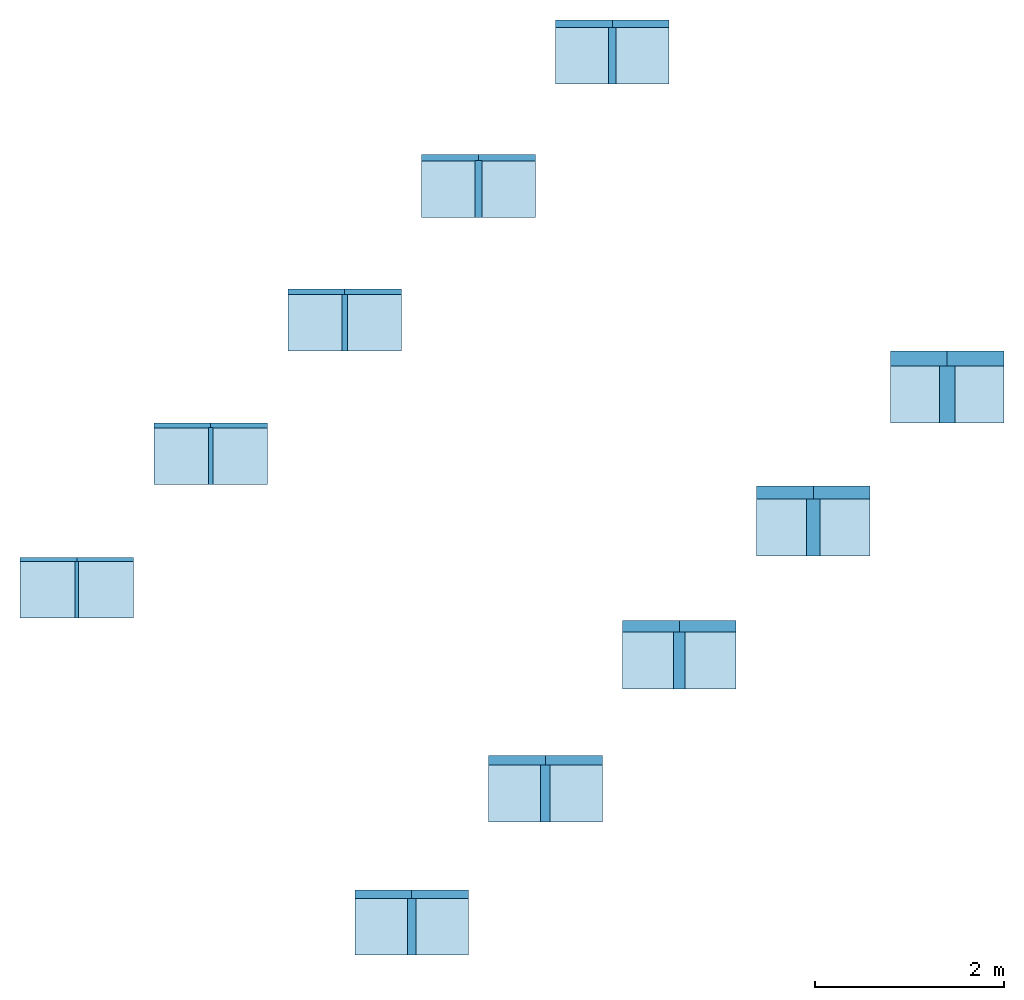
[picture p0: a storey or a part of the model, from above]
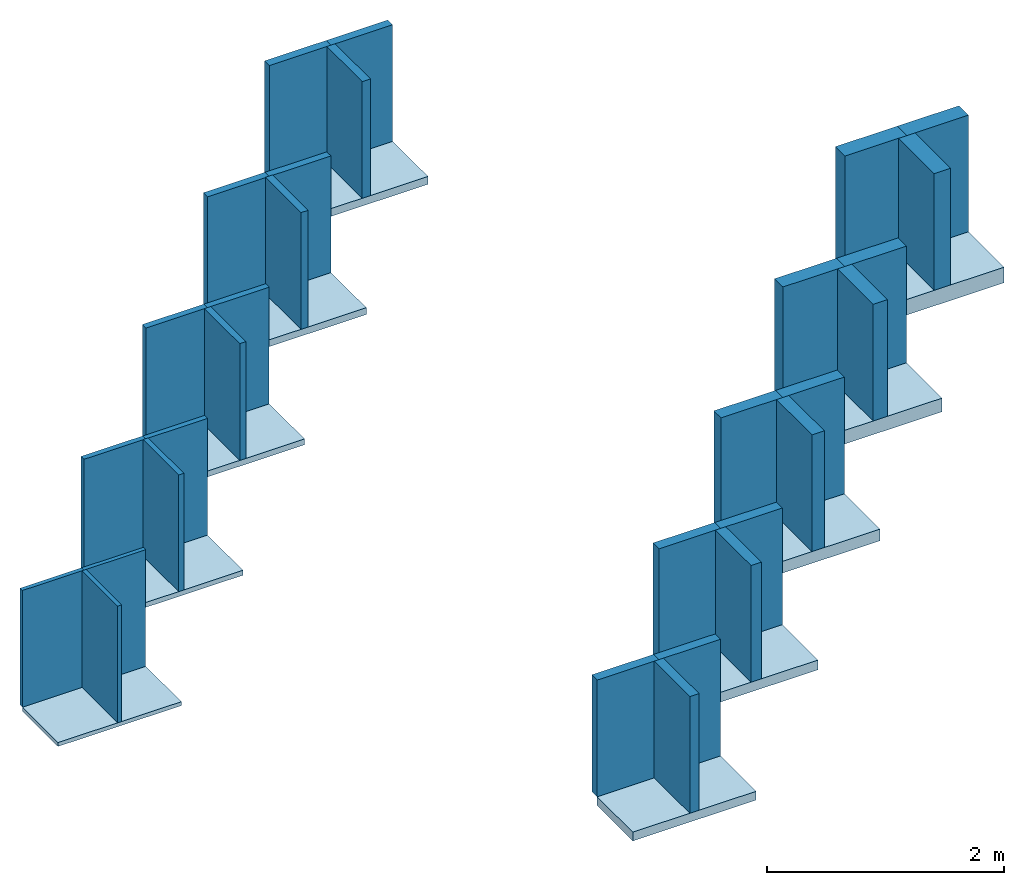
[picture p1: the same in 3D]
Properties of the parts of a building model (IFC2X3), part 1 of 2

# File
Description: ViewDefinition [CoordinationView]
Time: 2023-01-18T13:19:17
Written by: The EXPRESS Data Manager Version 5.02.0100.07 : 28 Aug 2013
Made in: 21.1.70.21 - Exporter 21.1.70.21 - Alternate UI 21.1.70.21
Comment: STEP Physical File produced by: The EXPRESS Data Manager Version 5.02.0100.07 : 28 Aug 2013 * Module: EDMstepFileFactory/EDMstandAlone * Creation date: Wed Jan 18 13:19:17 2023 * Host: BIM-LT03 * Database: C:\Users\DONNEE~1\AppData\Local\Temp\6dfd9f73-01cb-4fe2-bb7c-203e315a706e\f2f63303-374b-483b-9fe5-4dce5f40f722\ifc * Database version: 5507 * Database creation date: Wed Jan 18 13:19:16 2023 * Schema: IFC2X3 * Model: DataRepository.ifc * Model creation date: Wed Jan 18 13:19:16 2023 * Header model: DataRepository.ifc_HeaderModel * Header model creation date: Wed Jan 18 13:19:16 2023 * EDMuser: sdai-user * EDMgroup: sdai-group * License ID and type: 5605 : Permanent license. Expiry date: * EDMstepFileFactory options: 020000

# IfcSite, Default
RefLatitude: 42, 24, 53, 508911; RefLongitude: -71, -15, -29, -58837; RefElevation: 0 mm
Pset_ProductRequirements - Category: Project Information

# IfcBuilding
Pset_BuildingCommon - NumberOfStoreys: 2
Pset_ProductRequirements - Category: Project Information

# IfcBuildingStorey: Level:NL_00_niveau (2)
Pset_ProductRequirements - Category: Levels
Name | LongName = Pset_AirSideSystemInformation, Name = Pset_ProductRequirements, Name | Elevation (mm)
Begane grond | Begane grond | 0
lengte 1200 | lengte 1200 | 1200

# IfcRoof: Basic Roof:NLRS_27_RO_Rock4all_100x600x1200mm, Basic Roof:NLRS_27_RO_Rock4all_100x600x1200mm:5487
In: lengte 1200
Classification: 27 Daken (Uniformat)
Pset_ElementShading - Roughness: 304.8 mm
Pset_ManufacturerTypeInformation - Manufacturer: Knauf Insulation B.V.
Pset_ProductRequirements - Category: Roofs
Pset_QuantityTakeOff - Reference: Basic Roof:NLRS_27_RO_Rock4all_100x600x1200mm
Pset_RoofCommon - IsExternal: yes; Reference: Basic Roof:NLRS_27_RO_Rock4all_100x600x1200mm; ProjectedArea: 0.72 m2; TotalArea: 0.72 m2
Pset_Roof Schedule Rock4All LOD400 - platen / pak: 5; Type: Basic Roof: NLRS_27_RO_Rock4all_100x600x1200mm; Assembly Code: 27; Type Image: Raster image: Rock4all_KL.jpg (3); Model: Rock4All is een onbeklede steenwolplaat met ECOSE® Technology; Manufacturer: Knauf Insulation B.V.; URL: www.knaufinsulation.nl; Description: Rock4all - 100mm; phone: +31(0)162-421245; email: customerservice.nl@knaufinsulation.com; product URL: https://www.knaufinsulation.nl/producten-van-knauf-insulation/Rock4All; warmteweerstand: 2.85; NLRS_C_Code_Brandklasse: A1; warmtegeleidingscoëfficiënt: 0.035; waterdamptransmissie / waterdampdiffusie weerstandsfactor: MU1; luchtstroomweerstand: Afr5; DoP nummer (Declaration of performance): R4208LPCPR; diktebereik: 20-200; diktetolerantie: T4; pak (m2): 3.6; pakken / pallet: 12; pallet (m2): 43.2

# IfcRoof: Basic Roof:NLRS_27_RO_Rock4all_120x600x1200mm, Basic Roof:NLRS_27_RO_Rock4all_120x600x1200mm:5557
In: lengte 1200
Classification: 27 Daken (Uniformat)
Pset_ElementShading - Roughness: 304.8 mm
Pset_ManufacturerTypeInformation - Manufacturer: Knauf Insulation B.V.
Pset_ProductRequirements - Category: Roofs
Pset_QuantityTakeOff - Reference: Basic Roof:NLRS_27_RO_Rock4all_120x600x1200mm
Pset_RoofCommon - IsExternal: yes; Reference: Basic Roof:NLRS_27_RO_Rock4all_120x600x1200mm; ProjectedArea: 0.72 m2; TotalArea: 0.72 m2
Pset_Roof Schedule Rock4All LOD400 - platen / pak: 4; Type: Basic Roof: NLRS_27_RO_Rock4all_120x600x1200mm; Assembly Code: 27; Type Image: Raster image: Rock4all_KL.jpg (3); Model: Rock4All is een onbeklede steenwolplaat met ECOSE® Technology; Manufacturer: Knauf Insulation B.V.; URL: www.knaufinsulation.nl; Description: Rock4all - 120mm; phone: +31(0)162-421245; email: customerservice.nl@knaufinsulation.com; product URL: https://www.knaufinsulation.nl/producten-van-knauf-insulation/Rock4All; warmteweerstand: 3.4; NLRS_C_Code_Brandklasse: A1; warmtegeleidingscoëfficiënt: 0.035; waterdamptransmissie / waterdampdiffusie weerstandsfactor: MU1; luchtstroomweerstand: Afr5; DoP nummer (Declaration of performance): R4208LPCPR; diktebereik: 20-200; diktetolerantie: T4; pak (m2): 2.88; pakken / pallet: 12; pallet (m2): 34.56

# IfcRoof: Basic Roof:NLRS_27_RO_Rock4all_140x600x1200mm, Basic Roof:NLRS_27_RO_Rock4all_140x600x1200mm:5576
In: lengte 1200
Classification: 27 Daken (Uniformat)
Pset_ElementShading - Roughness: 304.8 mm
Pset_ManufacturerTypeInformation - Manufacturer: Knauf Insulation B.V.
Pset_ProductRequirements - Category: Roofs
Pset_QuantityTakeOff - Reference: Basic Roof:NLRS_27_RO_Rock4all_140x600x1200mm
Pset_RoofCommon - IsExternal: yes; Reference: Basic Roof:NLRS_27_RO_Rock4all_140x600x1200mm; ProjectedArea: 0.72 m2; TotalArea: 0.72 m2
Pset_Roof Schedule Rock4All LOD400 - warmteweerstand: 4; platen / pak: 3; Type: Basic Roof: NLRS_27_RO_Rock4all_140x600x1200mm; Assembly Code: 27; Type Image: Raster image: Rock4all_KL.jpg (3); Model: Rock4All is een onbeklede steenwolplaat met ECOSE® Technology; Manufacturer: Knauf Insulation B.V.; URL: www.knaufinsulation.nl; Description: Rock4all - 140mm; phone: +31(0)162-421245; email: customerservice.nl@knaufinsulation.com; product URL: https://www.knaufinsulation.nl/producten-van-knauf-insulation/Rock4All; NLRS_C_Code_Brandklasse: A1; warmtegeleidingscoëfficiënt: 0.035; waterdamptransmissie / waterdampdiffusie weerstandsfactor: MU1; luchtstroomweerstand: Afr5; DoP nummer (Declaration of performance): R4208LPCPR; diktebereik: 20-200; diktetolerantie: T4; pak (m2): 2.16; pakken / pallet: 12; pallet (m2): 25.92

# IfcRoof: Basic Roof:NLRS_27_RO_Rock4all_160x600x1200mm, Basic Roof:NLRS_27_RO_Rock4all_160x600x1200mm:5595
In: lengte 1200
Classification: 27 Daken (Uniformat)
Pset_ElementShading - Roughness: 304.8 mm
Pset_ManufacturerTypeInformation - Manufacturer: Knauf Insulation B.V.
Pset_ProductRequirements - Category: Roofs
Pset_QuantityTakeOff - Reference: Basic Roof:NLRS_27_RO_Rock4all_160x600x1200mm
Pset_RoofCommon - IsExternal: yes; Reference: Basic Roof:NLRS_27_RO_Rock4all_160x600x1200mm; ProjectedArea: 0.72 m2; TotalArea: 0.72 m2
Pset_Roof Schedule Rock4All LOD400 - platen / pak: 3; Type: Basic Roof: NLRS_27_RO_Rock4all_160x600x1200mm; Assembly Code: 27; Type Image: Raster image: Rock4all_KL.jpg (3); Model: Rock4All is een onbeklede steenwolplaat met ECOSE® Technology; Manufacturer: Knauf Insulation B.V.; URL: www.knaufinsulation.nl; Description: Rock4all - 160mm; phone: +31(0)162-421245; email: customerservice.nl@knaufinsulation.com; product URL: https://www.knaufinsulation.nl/producten-van-knauf-insulation/Rock4All; warmteweerstand: 4.55; NLRS_C_Code_Brandklasse: A1; warmtegeleidingscoëfficiënt: 0.035; waterdamptransmissie / waterdampdiffusie weerstandsfactor: MU1; luchtstroomweerstand: Afr5; DoP nummer (Declaration of performance): R4208LPCPR; diktebereik: 20-200; diktetolerantie: T4; pak (m2): 2.16; pakken / pallet: 12; pallet (m2): 25.92

# IfcRoof: Basic Roof:NLRS_27_RO_Rock4all_40x600x1200mm, Basic Roof:NLRS_27_RO_Rock4all_40x600x1200mm:5042
In: lengte 1200
Classification: 27 Daken (Uniformat)
Pset_ElementShading - Roughness: 304.8 mm
Pset_ManufacturerTypeInformation - Manufacturer: Knauf Insulation B.V.
Pset_ProductRequirements - Category: Roofs
Pset_QuantityTakeOff - Reference: Basic Roof:NLRS_27_RO_Rock4all_40x600x1200mm
Pset_RoofCommon - Reference: Basic Roof:NLRS_27_RO_Rock4all_40x600x1200mm; IsExternal: yes; ProjectedArea: 0.72 m2; TotalArea: 0.72 m2
Pset_Roof Schedule Rock4All LOD400 - Type: Basic Roof: NLRS_27_RO_Rock4all_40x600x1200mm; Assembly Code: 27; Type Image: Raster image: Rock4all_KL.jpg (3); Model: Rock4All is een onbeklede steenwolplaat met ECOSE® Technology; Manufacturer: Knauf Insulation B.V.; URL: www.knaufinsulation.nl; Description: Rock4all - 40mm; phone: +31(0)162-421245; email: customerservice.nl@knaufinsulation.com; product URL: https://www.knaufinsulation.nl/producten-van-knauf-insulation/Rock4All; warmteweerstand: 1.1; NLRS_C_Code_Brandklasse: A1; warmtegeleidingscoëfficiënt: 0.035; waterdamptransmissie / waterdampdiffusie weerstandsfactor: MU1; luchtstroomweerstand: Afr5; DoP nummer (Declaration of performance): R4208LPCPR; diktebereik: 20-200; diktetolerantie: T4; platen / pak: 12; pak (m2): 8.64; pakken / pallet: 12; pallet (m2): 103.68

# IfcRoof: Basic Roof:NLRS_27_RO_Rock4all_50x600x1200mm, Basic Roof:NLRS_27_RO_Rock4all_50x600x1200mm:5238
In: lengte 1200
Classification: 27 Daken (Uniformat)
Pset_ElementShading - Roughness: 304.8 mm
Pset_ManufacturerTypeInformation - Manufacturer: Knauf Insulation B.V.
Pset_ProductRequirements - Category: Roofs
Pset_QuantityTakeOff - Reference: Basic Roof:NLRS_27_RO_Rock4all_50x600x1200mm
Pset_RoofCommon - IsExternal: yes; Reference: Basic Roof:NLRS_27_RO_Rock4all_50x600x1200mm; ProjectedArea: 0.72 m2; TotalArea: 0.72 m2
Pset_Roof Schedule Rock4All LOD400 - platen / pak: 10; Type: Basic Roof: NLRS_27_RO_Rock4all_50x600x1200mm; Assembly Code: 27; Type Image: Raster image: Rock4all_KL.jpg (3); Model: Rock4All is een onbeklede steenwolplaat met ECOSE® Technology; Manufacturer: Knauf Insulation B.V.; URL: www.knaufinsulation.nl; Description: Rock4all - 50mm; phone: +31(0)162-421245; email: customerservice.nl@knaufinsulation.com; product URL: https://www.knaufinsulation.nl/producten-van-knauf-insulation/Rock4All; warmteweerstand: 1.4; NLRS_C_Code_Brandklasse: A1; warmtegeleidingscoëfficiënt: 0.035; waterdamptransmissie / waterdampdiffusie weerstandsfactor: MU1; luchtstroomweerstand: Afr5; DoP nummer (Declaration of performance): R4208LPCPR; diktebereik: 20-200; diktetolerantie: T4; pak (m2): 7.2; pakken / pallet: 12; pallet (m2): 86.4

# IfcRoof: Basic Roof:NLRS_27_RO_Rock4all_60x600x1200mm, Basic Roof:NLRS_27_RO_Rock4all_60x600x1200mm:5266
In: lengte 1200
Classification: 27 Daken (Uniformat)
Pset_ElementShading - Roughness: 304.8 mm
Pset_ManufacturerTypeInformation - Manufacturer: Knauf Insulation B.V.
Pset_ProductRequirements - Category: Roofs
Pset_QuantityTakeOff - Reference: Basic Roof:NLRS_27_RO_Rock4all_60x600x1200mm
Pset_RoofCommon - IsExternal: yes; Reference: Basic Roof:NLRS_27_RO_Rock4all_60x600x1200mm; ProjectedArea: 0.72 m2; TotalArea: 0.72 m2
Pset_Roof Schedule Rock4All LOD400 - platen / pak: 8; Type: Basic Roof: NLRS_27_RO_Rock4all_60x600x1200mm; Assembly Code: 27; Type Image: Raster image: Rock4all_KL.jpg (3); Model: Rock4All is een onbeklede steenwolplaat met ECOSE® Technology; Manufacturer: Knauf Insulation B.V.; URL: www.knaufinsulation.nl; Description: Rock4all - 60mm; phone: +31(0)162-421245; email: customerservice.nl@knaufinsulation.com; product URL: https://www.knaufinsulation.nl/producten-van-knauf-insulation/Rock4All; warmteweerstand: 1.7; NLRS_C_Code_Brandklasse: A1; warmtegeleidingscoëfficiënt: 0.035; waterdamptransmissie / waterdampdiffusie weerstandsfactor: MU1; luchtstroomweerstand: Afr5; DoP nummer (Declaration of performance): R4208LPCPR; diktebereik: 20-200; diktetolerantie: T4; pak (m2): 5.76; pakken / pallet: 12; pallet (m2): 69.12

# IfcRoof: Basic Roof:NLRS_27_RO_Rock4all_70x600x1200mm, Basic Roof:NLRS_27_RO_Rock4all_70x600x1200mm:5292
In: lengte 1200
Classification: 27 Daken (Uniformat)
Pset_ElementShading - Roughness: 304.8 mm
Pset_ManufacturerTypeInformation - Manufacturer: Knauf Insulation B.V.
Pset_ProductRequirements - Category: Roofs
Pset_QuantityTakeOff - Reference: Basic Roof:NLRS_27_RO_Rock4all_70x600x1200mm
Pset_RoofCommon - IsExternal: yes; Reference: Basic Roof:NLRS_27_RO_Rock4all_70x600x1200mm; ProjectedArea: 0.72 m2; TotalArea: 0.72 m2
Pset_Roof Schedule Rock4All LOD400 - warmteweerstand: 2; platen / pak: 6; Type: Basic Roof: NLRS_27_RO_Rock4all_70x600x1200mm; Assembly Code: 27; Type Image: Raster image: Rock4all_KL.jpg (3); Model: Rock4All is een onbeklede steenwolplaat met ECOSE® Technology; Manufacturer: Knauf Insulation B.V.; URL: www.knaufinsulation.nl; Description: Rock4all - 70mm; phone: +31(0)162-421245; email: customerservice.nl@knaufinsulation.com; product URL: https://www.knaufinsulation.nl/producten-van-knauf-insulation/Rock4All; NLRS_C_Code_Brandklasse: A1; warmtegeleidingscoëfficiënt: 0.035; waterdamptransmissie / waterdampdiffusie weerstandsfactor: MU1; luchtstroomweerstand: Afr5; DoP nummer (Declaration of performance): R4208LPCPR; diktebereik: 20-200; diktetolerantie: T4; pak (m2): 4.32; pakken / pallet: 12; pallet (m2): 51.84

# IfcRoof: Basic Roof:NLRS_27_RO_Rock4all_80x600x1200mm, Basic Roof:NLRS_27_RO_Rock4all_80x600x1200mm:5303
In: lengte 1200
Classification: 27 Daken (Uniformat)
Pset_ElementShading - Roughness: 304.8 mm
Pset_ManufacturerTypeInformation - Manufacturer: Knauf Insulation B.V.
Pset_ProductRequirements - Category: Roofs
Pset_QuantityTakeOff - Reference: Basic Roof:NLRS_27_RO_Rock4all_80x600x1200mm
Pset_RoofCommon - IsExternal: yes; Reference: Basic Roof:NLRS_27_RO_Rock4all_80x600x1200mm; ProjectedArea: 0.72 m2; TotalArea: 0.72 m2
Pset_Roof Schedule Rock4All LOD400 - platen / pak: 6; Type: Basic Roof: NLRS_27_RO_Rock4all_80x600x1200mm; Assembly Code: 27; Type Image: Raster image: Rock4all_KL.jpg (3); Model: Rock4All is een onbeklede steenwolplaat met ECOSE® Technology; Manufacturer: Knauf Insulation B.V.; URL: www.knaufinsulation.nl; Description: Rock4all - 80mm; phone: +31(0)162-421245; email: customerservice.nl@knaufinsulation.com; product URL: https://www.knaufinsulation.nl/producten-van-knauf-insulation/Rock4All; warmteweerstand: 2.25; NLRS_C_Code_Brandklasse: A1; warmtegeleidingscoëfficiënt: 0.035; waterdamptransmissie / waterdampdiffusie weerstandsfactor: MU1; luchtstroomweerstand: Afr5; DoP nummer (Declaration of performance): R4208LPCPR; diktebereik: 20-200; diktetolerantie: T4; pak (m2): 4.32; pakken / pallet: 12; pallet (m2): 51.84

# IfcRoof: Basic Roof:NLRS_27_RO_Rock4all_90x600x1200mm, Basic Roof:NLRS_27_RO_Rock4all_90x600x1200mm:5462
In: lengte 1200
Classification: 27 Daken (Uniformat)
Pset_ElementShading - Roughness: 304.8 mm
Pset_ManufacturerTypeInformation - Manufacturer: Knauf Insulation B.V.
Pset_ProductRequirements - Category: Roofs
Pset_QuantityTakeOff - Reference: Basic Roof:NLRS_27_RO_Rock4all_90x600x1200mm
Pset_RoofCommon - IsExternal: yes; Reference: Basic Roof:NLRS_27_RO_Rock4all_90x600x1200mm; ProjectedArea: 0.72 m2; TotalArea: 0.72 m2
Pset_Roof Schedule Rock4All LOD400 - platen / pak: 5; Type: Basic Roof: NLRS_27_RO_Rock4all_90x600x1200mm; Assembly Code: 27; Type Image: Raster image: Rock4all_KL.jpg (3); Model: Rock4All is een onbeklede steenwolplaat met ECOSE® Technology; Manufacturer: Knauf Insulation B.V.; URL: www.knaufinsulation.nl; Description: Rock4all - 90mm; phone: +31(0)162-421245; email: customerservice.nl@knaufinsulation.com; product URL: https://www.knaufinsulation.nl/producten-van-knauf-insulation/Rock4All; warmteweerstand: 2.55; NLRS_C_Code_Brandklasse: A1; warmtegeleidingscoëfficiënt: 0.035; waterdamptransmissie / waterdampdiffusie weerstandsfactor: MU1; luchtstroomweerstand: Afr5; DoP nummer (Declaration of performance): R4208LPCPR; diktebereik: 20-200; diktetolerantie: T4; pak (m2): 3.6; pakken / pallet: 12; pallet (m2): 43.2

# IfcSlab: Basic Roof:NLRS_27_RO_Rock4all_100x600x1200mm, Basic Roof:NLRS_27_RO_Rock4all_100x600x1200mm:5487
In: lengte 1200
Type - PredefinedType: ROOF
Type - Pset_ElementShading - Roughness: 304.8 mm
Type - Pset_ManufacturerTypeInformation - Manufacturer: Knauf Insulation B.V.
Type - Pset_ProductRequirements - Category: Roofs
Type - Pset_QuantityTakeOff - Reference: Basic Roof:NLRS_27_RO_Rock4all_100x600x1200mm
Type - Pset_ReinforcementBarPitchOfSlab - Description: Rock4all - 100mm; Reference: Basic Roof:NLRS_27_RO_Rock4all_100x600x1200mm
Type - Pset_SlabCommon - ThermalTransmittance: 0.35 kg/K/s3; IsExternal: yes; Reference: Basic Roof:NLRS_27_RO_Rock4all_100x600x1200mm
Type - Pset_Roof Schedule Rock4All LOD400 - platen / pak: 5; Assembly Code: 27; Type Image: Raster image: Rock4all_KL.jpg (3); Model: Rock4All is een onbeklede steenwolplaat met ECOSE® Technology; Manufacturer: Knauf Insulation B.V.; URL: www.knaufinsulation.nl; Description: Rock4all - 100mm; phone: +31(0)162-421245; email: customerservice.nl@knaufinsulation.com; product URL: https://www.knaufinsulation.nl/producten-van-knauf-insulation/Rock4All; warmteweerstand: 2.85; NLRS_C_Code_Brandklasse: A1; warmtegeleidingscoëfficiënt: 0.035; waterdamptransmissie / waterdampdiffusie weerstandsfactor: MU1; luchtstroomweerstand: Afr5; DoP nummer (Declaration of performance): R4208LPCPR; diktebereik: 20-200; diktetolerantie: T4; pak (m2): 3.6; pakken / pallet: 12; pallet (m2): 43.2
Classification: 27 Daken (Uniformat); Material: Knauf Insulation_Ecose® steenwol Rock4All; Knauf Insulation_Ecose® steenwol Rock4All 100 mm
Pset_SlabCommon - PitchAngle: 0 deg
Pset_Roof Schedule Rock4All LOD400 - Type: Basic Roof: NLRS_27_RO_Rock4all_100x600x1200mm

# IfcSlab: Basic Roof:NLRS_27_RO_Rock4all_120x600x1200mm, Basic Roof:NLRS_27_RO_Rock4all_120x600x1200mm:5557
In: lengte 1200
Type - PredefinedType: ROOF
Type - Pset_ElementShading - Roughness: 304.8 mm
Type - Pset_ManufacturerTypeInformation - Manufacturer: Knauf Insulation B.V.
Type - Pset_ProductRequirements - Category: Roofs
Type - Pset_QuantityTakeOff - Reference: Basic Roof:NLRS_27_RO_Rock4all_120x600x1200mm
Type - Pset_ReinforcementBarPitchOfSlab - Description: Rock4all - 120mm; Reference: Basic Roof:NLRS_27_RO_Rock4all_120x600x1200mm
Type - Pset_SlabCommon - IsExternal: yes; Reference: Basic Roof:NLRS_27_RO_Rock4all_120x600x1200mm; ThermalTransmittance: 0.291667 kg/K/s3
Type - Pset_Roof Schedule Rock4All LOD400 - platen / pak: 4; Assembly Code: 27; Type Image: Raster image: Rock4all_KL.jpg (3); Model: Rock4All is een onbeklede steenwolplaat met ECOSE® Technology; Manufacturer: Knauf Insulation B.V.; URL: www.knaufinsulation.nl; Description: Rock4all - 120mm; phone: +31(0)162-421245; email: customerservice.nl@knaufinsulation.com; product URL: https://www.knaufinsulation.nl/producten-van-knauf-insulation/Rock4All; warmteweerstand: 3.4; NLRS_C_Code_Brandklasse: A1; warmtegeleidingscoëfficiënt: 0.035; waterdamptransmissie / waterdampdiffusie weerstandsfactor: MU1; luchtstroomweerstand: Afr5; DoP nummer (Declaration of performance): R4208LPCPR; diktebereik: 20-200; diktetolerantie: T4; pak (m2): 2.88; pakken / pallet: 12; pallet (m2): 34.56
Classification: 27 Daken (Uniformat); Material: Knauf Insulation_Ecose® steenwol Rock4All; Knauf Insulation_Ecose® steenwol Rock4All 120 mm
Pset_SlabCommon - PitchAngle: 0 deg
Pset_Roof Schedule Rock4All LOD400 - Type: Basic Roof: NLRS_27_RO_Rock4all_120x600x1200mm

# IfcSlab: Basic Roof:NLRS_27_RO_Rock4all_140x600x1200mm, Basic Roof:NLRS_27_RO_Rock4all_140x600x1200mm:5576
In: lengte 1200
Type - PredefinedType: ROOF
Type - Pset_ElementShading - Roughness: 304.8 mm
Type - Pset_ManufacturerTypeInformation - Manufacturer: Knauf Insulation B.V.
Type - Pset_ProductRequirements - Category: Roofs
Type - Pset_QuantityTakeOff - Reference: Basic Roof:NLRS_27_RO_Rock4all_140x600x1200mm
Type - Pset_ReinforcementBarPitchOfSlab - Description: Rock4all - 140mm; Reference: Basic Roof:NLRS_27_RO_Rock4all_140x600x1200mm
Type - Pset_SlabCommon - ThermalTransmittance: 0.25 kg/K/s3; IsExternal: yes; Reference: Basic Roof:NLRS_27_RO_Rock4all_140x600x1200mm
Type - Pset_Roof Schedule Rock4All LOD400 - warmteweerstand: 4; platen / pak: 3; Assembly Code: 27; Type Image: Raster image: Rock4all_KL.jpg (3); Model: Rock4All is een onbeklede steenwolplaat met ECOSE® Technology; Manufacturer: Knauf Insulation B.V.; URL: www.knaufinsulation.nl; Description: Rock4all - 140mm; phone: +31(0)162-421245; email: customerservice.nl@knaufinsulation.com; product URL: https://www.knaufinsulation.nl/producten-van-knauf-insulation/Rock4All; NLRS_C_Code_Brandklasse: A1; warmtegeleidingscoëfficiënt: 0.035; waterdamptransmissie / waterdampdiffusie weerstandsfactor: MU1; luchtstroomweerstand: Afr5; DoP nummer (Declaration of performance): R4208LPCPR; diktebereik: 20-200; diktetolerantie: T4; pak (m2): 2.16; pakken / pallet: 12; pallet (m2): 25.92
Classification: 27 Daken (Uniformat); Material: Knauf Insulation_Ecose® steenwol Rock4All; Knauf Insulation_Ecose® steenwol Rock4All 140 mm
Pset_SlabCommon - PitchAngle: 0 deg
Pset_Roof Schedule Rock4All LOD400 - Type: Basic Roof: NLRS_27_RO_Rock4all_140x600x1200mm

# IfcSlab: Basic Roof:NLRS_27_RO_Rock4all_160x600x1200mm, Basic Roof:NLRS_27_RO_Rock4all_160x600x1200mm:5595
In: lengte 1200
Type - PredefinedType: ROOF
Type - Pset_ElementShading - Roughness: 304.8 mm
Type - Pset_ManufacturerTypeInformation - Manufacturer: Knauf Insulation B.V.
Type - Pset_ProductRequirements - Category: Roofs
Type - Pset_QuantityTakeOff - Reference: Basic Roof:NLRS_27_RO_Rock4all_160x600x1200mm
Type - Pset_ReinforcementBarPitchOfSlab - Description: Rock4all - 160mm; Reference: Basic Roof:NLRS_27_RO_Rock4all_160x600x1200mm
Type - Pset_SlabCommon - IsExternal: yes; Reference: Basic Roof:NLRS_27_RO_Rock4all_160x600x1200mm; ThermalTransmittance: 0.21875 kg/K/s3
Type - Pset_Roof Schedule Rock4All LOD400 - platen / pak: 3; Assembly Code: 27; Type Image: Raster image: Rock4all_KL.jpg (3); Model: Rock4All is een onbeklede steenwolplaat met ECOSE® Technology; Manufacturer: Knauf Insulation B.V.; URL: www.knaufinsulation.nl; Description: Rock4all - 160mm; phone: +31(0)162-421245; email: customerservice.nl@knaufinsulation.com; product URL: https://www.knaufinsulation.nl/producten-van-knauf-insulation/Rock4All; warmteweerstand: 4.55; NLRS_C_Code_Brandklasse: A1; warmtegeleidingscoëfficiënt: 0.035; waterdamptransmissie / waterdampdiffusie weerstandsfactor: MU1; luchtstroomweerstand: Afr5; DoP nummer (Declaration of performance): R4208LPCPR; diktebereik: 20-200; diktetolerantie: T4; pak (m2): 2.16; pakken / pallet: 12; pallet (m2): 25.92
Classification: 27 Daken (Uniformat); Material: Knauf Insulation_Ecose® steenwol Rock4All; Knauf Insulation_Ecose® steenwol Rock4All 160 mm
Pset_SlabCommon - PitchAngle: 0 deg
Pset_Roof Schedule Rock4All LOD400 - Type: Basic Roof: NLRS_27_RO_Rock4all_160x600x1200mm

# IfcSlab: Basic Roof:NLRS_27_RO_Rock4all_40x600x1200mm, Basic Roof:NLRS_27_RO_Rock4all_40x600x1200mm:5042
In: lengte 1200
Type - PredefinedType: ROOF
Type - Pset_ElementShading - Roughness: 304.8 mm
Type - Pset_ManufacturerTypeInformation - Manufacturer: Knauf Insulation B.V.
Type - Pset_ProductRequirements - Category: Roofs
Type - Pset_QuantityTakeOff - Reference: Basic Roof:NLRS_27_RO_Rock4all_40x600x1200mm
Type - Pset_ReinforcementBarPitchOfSlab - Description: Rock4all - 40mm; Reference: Basic Roof:NLRS_27_RO_Rock4all_40x600x1200mm
Type - Pset_SlabCommon - Reference: Basic Roof:NLRS_27_RO_Rock4all_40x600x1200mm; IsExternal: yes; ThermalTransmittance: 0.875 kg/K/s3
Type - Pset_Roof Schedule Rock4All LOD400 - Assembly Code: 27; Type Image: Raster image: Rock4all_KL.jpg (3); Model: Rock4All is een onbeklede steenwolplaat met ECOSE® Technology; Manufacturer: Knauf Insulation B.V.; URL: www.knaufinsulation.nl; Description: Rock4all - 40mm; phone: +31(0)162-421245; email: customerservice.nl@knaufinsulation.com; product URL: https://www.knaufinsulation.nl/producten-van-knauf-insulation/Rock4All; warmteweerstand: 1.1; NLRS_C_Code_Brandklasse: A1; warmtegeleidingscoëfficiënt: 0.035; waterdamptransmissie / waterdampdiffusie weerstandsfactor: MU1; luchtstroomweerstand: Afr5; DoP nummer (Declaration of performance): R4208LPCPR; diktebereik: 20-200; diktetolerantie: T4; platen / pak: 12; pak (m2): 8.64; pakken / pallet: 12; pallet (m2): 103.68
Classification: 27 Daken (Uniformat); Material: Knauf Insulation_Ecose® steenwol Rock4All; Knauf Insulation_Ecose® steenwol Rock4All 40 mm
Pset_SlabCommon - PitchAngle: 0 deg
Pset_Roof Schedule Rock4All LOD400 - Type: Basic Roof: NLRS_27_RO_Rock4all_40x600x1200mm

# IfcSlab: Basic Roof:NLRS_27_RO_Rock4all_50x600x1200mm, Basic Roof:NLRS_27_RO_Rock4all_50x600x1200mm:5238
In: lengte 1200
Type - PredefinedType: ROOF
Type - Pset_ElementShading - Roughness: 304.8 mm
Type - Pset_ManufacturerTypeInformation - Manufacturer: Knauf Insulation B.V.
Type - Pset_ProductRequirements - Category: Roofs
Type - Pset_QuantityTakeOff - Reference: Basic Roof:NLRS_27_RO_Rock4all_50x600x1200mm
Type - Pset_ReinforcementBarPitchOfSlab - Description: Rock4all - 50mm; Reference: Basic Roof:NLRS_27_RO_Rock4all_50x600x1200mm
Type - Pset_SlabCommon - ThermalTransmittance: 0.7 kg/K/s3; IsExternal: yes; Reference: Basic Roof:NLRS_27_RO_Rock4all_50x600x1200mm
Type - Pset_Roof Schedule Rock4All LOD400 - platen / pak: 10; Assembly Code: 27; Type Image: Raster image: Rock4all_KL.jpg (3); Model: Rock4All is een onbeklede steenwolplaat met ECOSE® Technology; Manufacturer: Knauf Insulation B.V.; URL: www.knaufinsulation.nl; Description: Rock4all - 50mm; phone: +31(0)162-421245; email: customerservice.nl@knaufinsulation.com; product URL: https://www.knaufinsulation.nl/producten-van-knauf-insulation/Rock4All; warmteweerstand: 1.4; NLRS_C_Code_Brandklasse: A1; warmtegeleidingscoëfficiënt: 0.035; waterdamptransmissie / waterdampdiffusie weerstandsfactor: MU1; luchtstroomweerstand: Afr5; DoP nummer (Declaration of performance): R4208LPCPR; diktebereik: 20-200; diktetolerantie: T4; pak (m2): 7.2; pakken / pallet: 12; pallet (m2): 86.4
Classification: 27 Daken (Uniformat); Material: Knauf Insulation_Ecose® steenwol Rock4All; Knauf Insulation_Ecose® steenwol Rock4All 50 mm
Pset_SlabCommon - PitchAngle: 0 deg
Pset_Roof Schedule Rock4All LOD400 - Type: Basic Roof: NLRS_27_RO_Rock4all_50x600x1200mm

# IfcSlab: Basic Roof:NLRS_27_RO_Rock4all_60x600x1200mm, Basic Roof:NLRS_27_RO_Rock4all_60x600x1200mm:5266
In: lengte 1200
Type - PredefinedType: ROOF
Type - Pset_ElementShading - Roughness: 304.8 mm
Type - Pset_ManufacturerTypeInformation - Manufacturer: Knauf Insulation B.V.
Type - Pset_ProductRequirements - Category: Roofs
Type - Pset_QuantityTakeOff - Reference: Basic Roof:NLRS_27_RO_Rock4all_60x600x1200mm
Type - Pset_ReinforcementBarPitchOfSlab - Description: Rock4all - 60mm; Reference: Basic Roof:NLRS_27_RO_Rock4all_60x600x1200mm
Type - Pset_SlabCommon - IsExternal: yes; Reference: Basic Roof:NLRS_27_RO_Rock4all_60x600x1200mm; ThermalTransmittance: 0.583333 kg/K/s3
Type - Pset_Roof Schedule Rock4All LOD400 - platen / pak: 8; Assembly Code: 27; Type Image: Raster image: Rock4all_KL.jpg (3); Model: Rock4All is een onbeklede steenwolplaat met ECOSE® Technology; Manufacturer: Knauf Insulation B.V.; URL: www.knaufinsulation.nl; Description: Rock4all - 60mm; phone: +31(0)162-421245; email: customerservice.nl@knaufinsulation.com; product URL: https://www.knaufinsulation.nl/producten-van-knauf-insulation/Rock4All; warmteweerstand: 1.7; NLRS_C_Code_Brandklasse: A1; warmtegeleidingscoëfficiënt: 0.035; waterdamptransmissie / waterdampdiffusie weerstandsfactor: MU1; luchtstroomweerstand: Afr5; DoP nummer (Declaration of performance): R4208LPCPR; diktebereik: 20-200; diktetolerantie: T4; pak (m2): 5.76; pakken / pallet: 12; pallet (m2): 69.12
Classification: 27 Daken (Uniformat); Material: Knauf Insulation_Ecose® steenwol Rock4All; Knauf Insulation_Ecose® steenwol Rock4All 60 mm
Pset_SlabCommon - PitchAngle: 0 deg
Pset_Roof Schedule Rock4All LOD400 - Type: Basic Roof: NLRS_27_RO_Rock4all_60x600x1200mm

# IfcSlab: Basic Roof:NLRS_27_RO_Rock4all_70x600x1200mm, Basic Roof:NLRS_27_RO_Rock4all_70x600x1200mm:5292
In: lengte 1200
Type - PredefinedType: ROOF
Type - Pset_ElementShading - Roughness: 304.8 mm
Type - Pset_ManufacturerTypeInformation - Manufacturer: Knauf Insulation B.V.
Type - Pset_ProductRequirements - Category: Roofs
Type - Pset_QuantityTakeOff - Reference: Basic Roof:NLRS_27_RO_Rock4all_70x600x1200mm
Type - Pset_ReinforcementBarPitchOfSlab - Description: Rock4all - 70mm; Reference: Basic Roof:NLRS_27_RO_Rock4all_70x600x1200mm
Type - Pset_SlabCommon - ThermalTransmittance: 0.5 kg/K/s3; IsExternal: yes; Reference: Basic Roof:NLRS_27_RO_Rock4all_70x600x1200mm
Type - Pset_Roof Schedule Rock4All LOD400 - warmteweerstand: 2; platen / pak: 6; Assembly Code: 27; Type Image: Raster image: Rock4all_KL.jpg (3); Model: Rock4All is een onbeklede steenwolplaat met ECOSE® Technology; Manufacturer: Knauf Insulation B.V.; URL: www.knaufinsulation.nl; Description: Rock4all - 70mm; phone: +31(0)162-421245; email: customerservice.nl@knaufinsulation.com; product URL: https://www.knaufinsulation.nl/producten-van-knauf-insulation/Rock4All; NLRS_C_Code_Brandklasse: A1; warmtegeleidingscoëfficiënt: 0.035; waterdamptransmissie / waterdampdiffusie weerstandsfactor: MU1; luchtstroomweerstand: Afr5; DoP nummer (Declaration of performance): R4208LPCPR; diktebereik: 20-200; diktetolerantie: T4; pak (m2): 4.32; pakken / pallet: 12; pallet (m2): 51.84
Classification: 27 Daken (Uniformat); Material: Knauf Insulation_Ecose® steenwol Rock4All; Knauf Insulation_Ecose® steenwol Rock4All 70 mm
Pset_SlabCommon - PitchAngle: 0 deg
Pset_Roof Schedule Rock4All LOD400 - Type: Basic Roof: NLRS_27_RO_Rock4all_70x600x1200mm

# IfcSlab: Basic Roof:NLRS_27_RO_Rock4all_80x600x1200mm, Basic Roof:NLRS_27_RO_Rock4all_80x600x1200mm:5303
In: lengte 1200
Type - PredefinedType: ROOF
Type - Pset_ElementShading - Roughness: 304.8 mm
Type - Pset_ManufacturerTypeInformation - Manufacturer: Knauf Insulation B.V.
Type - Pset_ProductRequirements - Category: Roofs
Type - Pset_QuantityTakeOff - Reference: Basic Roof:NLRS_27_RO_Rock4all_80x600x1200mm
Type - Pset_ReinforcementBarPitchOfSlab - Description: Rock4all - 80mm; Reference: Basic Roof:NLRS_27_RO_Rock4all_80x600x1200mm
Type - Pset_SlabCommon - IsExternal: yes; Reference: Basic Roof:NLRS_27_RO_Rock4all_80x600x1200mm; ThermalTransmittance: 0.4375 kg/K/s3
Type - Pset_Roof Schedule Rock4All LOD400 - platen / pak: 6; Assembly Code: 27; Type Image: Raster image: Rock4all_KL.jpg (3); Model: Rock4All is een onbeklede steenwolplaat met ECOSE® Technology; Manufacturer: Knauf Insulation B.V.; URL: www.knaufinsulation.nl; Description: Rock4all - 80mm; phone: +31(0)162-421245; email: customerservice.nl@knaufinsulation.com; product URL: https://www.knaufinsulation.nl/producten-van-knauf-insulation/Rock4All; warmteweerstand: 2.25; NLRS_C_Code_Brandklasse: A1; warmtegeleidingscoëfficiënt: 0.035; waterdamptransmissie / waterdampdiffusie weerstandsfactor: MU1; luchtstroomweerstand: Afr5; DoP nummer (Declaration of performance): R4208LPCPR; diktebereik: 20-200; diktetolerantie: T4; pak (m2): 4.32; pakken / pallet: 12; pallet (m2): 51.84
Classification: 27 Daken (Uniformat); Material: Knauf Insulation_Ecose® steenwol Rock4All; Knauf Insulation_Ecose® steenwol Rock4All 80 mm
Pset_SlabCommon - PitchAngle: 0 deg
Pset_Roof Schedule Rock4All LOD400 - Type: Basic Roof: NLRS_27_RO_Rock4all_80x600x1200mm

# IfcSlab: Basic Roof:NLRS_27_RO_Rock4all_90x600x1200mm, Basic Roof:NLRS_27_RO_Rock4all_90x600x1200mm:5462
In: lengte 1200
Type - PredefinedType: ROOF
Type - Pset_ElementShading - Roughness: 304.8 mm
Type - Pset_ManufacturerTypeInformation - Manufacturer: Knauf Insulation B.V.
Type - Pset_ProductRequirements - Category: Roofs
Type - Pset_QuantityTakeOff - Reference: Basic Roof:NLRS_27_RO_Rock4all_90x600x1200mm
Type - Pset_ReinforcementBarPitchOfSlab - Description: Rock4all - 90mm; Reference: Basic Roof:NLRS_27_RO_Rock4all_90x600x1200mm
Type - Pset_SlabCommon - IsExternal: yes; Reference: Basic Roof:NLRS_27_RO_Rock4all_90x600x1200mm; ThermalTransmittance: 0.388889 kg/K/s3
Type - Pset_Roof Schedule Rock4All LOD400 - platen / pak: 5; Assembly Code: 27; Type Image: Raster image: Rock4all_KL.jpg (3); Model: Rock4All is een onbeklede steenwolplaat met ECOSE® Technology; Manufacturer: Knauf Insulation B.V.; URL: www.knaufinsulation.nl; Description: Rock4all - 90mm; phone: +31(0)162-421245; email: customerservice.nl@knaufinsulation.com; product URL: https://www.knaufinsulation.nl/producten-van-knauf-insulation/Rock4All; warmteweerstand: 2.55; NLRS_C_Code_Brandklasse: A1; warmtegeleidingscoëfficiënt: 0.035; waterdamptransmissie / waterdampdiffusie weerstandsfactor: MU1; luchtstroomweerstand: Afr5; DoP nummer (Declaration of performance): R4208LPCPR; diktebereik: 20-200; diktetolerantie: T4; pak (m2): 3.6; pakken / pallet: 12; pallet (m2): 43.2
Classification: 27 Daken (Uniformat); Material: Knauf Insulation_Ecose® steenwol Rock4All; Knauf Insulation_Ecose® steenwol Rock4All 90 mm
Pset_SlabCommon - PitchAngle: 0 deg
Pset_Roof Schedule Rock4All LOD400 - Type: Basic Roof: NLRS_27_RO_Rock4all_90x600x1200mm

# IfcSlab: Floor:NLRS_23_FL_Rock4all_100x600x1200mm, Floor:NLRS_23_FL_Rock4all_100x600x1200mm:4768
In: Begane grond
Type - PredefinedType: FLOOR; Material: Knauf Insulation_Ecose® steenwol Rock4All 100 mm
Type - Pset_ElementShading - Roughness: 304.8 mm
Type - Pset_ManufacturerTypeInformation - Manufacturer: Knauf Insulation B.V.
Type - Pset_ProductRequirements - Category: Floors
Type - Pset_QuantityTakeOff - Reference: Floor:NLRS_23_FL_Rock4all_100x600x1200mm
Type - Pset_ReinforcementBarPitchOfSlab - Description: Rock4all - 100mm; Reference: Floor:NLRS_23_FL_Rock4all_100x600x1200mm
Type - Pset_SlabCommon - IsExternal: no; ThermalTransmittance: 0.35 kg/K/s3; Reference: Floor:NLRS_23_FL_Rock4all_100x600x1200mm
Type - Pset_Floor Schedule Rock4All LOD400 - platen / pak: 5; Assembly Code: 23; Type Image: Raster image: Rock4all_KL.jpg (3); Model: Rock4All is een onbeklede steenwolplaat met ECOSE® Technology Rock4All is een onbeklede steenwolplaat met ECOSE® Technology; Manufacturer: Knauf Insulation B.V.; URL: www.knaufinsulation.nl; Description: Rock4all - 100mm; phone: +31(0)162-421245; email: customerservice.nl@knaufinsulation.com; product URL: https://www.knaufinsulation.nl/producten-van-knauf-insulation/Rock4All; warmteweerstand: 2.85; NLRS_C_Code_Brandklasse: A1; warmtegeleidingscoëfficiënt: 0.035; waterdamptransmissie / waterdampdiffusie weerstandsfactor: MU1; luchtstroomweerstand: Afr5; DoP nummer (Declaration of performance): R4208LPCPR; NLRS_C_content_creator: Knauf Insulation; NLRS_C_content_versie: V1.0; diktebereik: 20-200; diktetolerantie: T4; pak (m2): 3.6; pakken / pallet: 12; pallet (m2): 43.2
Classification: 23 Vloeren (Uniformat)
Pset_SlabCommon - LoadBearing: no; PitchAngle: 0 deg
Pset_Floor Schedule Rock4All LOD400 - Type: Floor: NLRS_23_FL_Rock4all_100x600x1200mm

# IfcSlab: Floor:NLRS_23_FL_Rock4all_120x600x1200mm, Floor:NLRS_23_FL_Rock4all_120x600x1200mm:4821
In: Begane grond
Type - PredefinedType: FLOOR; Material: Knauf Insulation_Ecose® steenwol Rock4All 120 mm
Type - Pset_ElementShading - Roughness: 304.8 mm
Type - Pset_ManufacturerTypeInformation - Manufacturer: Knauf Insulation B.V.
Type - Pset_ProductRequirements - Category: Floors
Type - Pset_QuantityTakeOff - Reference: Floor:NLRS_23_FL_Rock4all_120x600x1200mm
Type - Pset_ReinforcementBarPitchOfSlab - Description: Rock4all - 120mm; Reference: Floor:NLRS_23_FL_Rock4all_120x600x1200mm
Type - Pset_SlabCommon - IsExternal: no; Reference: Floor:NLRS_23_FL_Rock4all_120x600x1200mm; ThermalTransmittance: 0.291667 kg/K/s3
Type - Pset_Floor Schedule Rock4All LOD400 - platen / pak: 4; Assembly Code: 23; Type Image: Raster image: Rock4all_KL.jpg (3); Model: Rock4All is een onbeklede steenwolplaat met ECOSE® Technology Rock4All is een onbeklede steenwolplaat met ECOSE® Technology; Manufacturer: Knauf Insulation B.V.; URL: www.knaufinsulation.nl; Description: Rock4all - 120mm; phone: +31(0)162-421245; email: customerservice.nl@knaufinsulation.com; product URL: https://www.knaufinsulation.nl/producten-van-knauf-insulation/Rock4All; warmteweerstand: 3.4; NLRS_C_Code_Brandklasse: A1; warmtegeleidingscoëfficiënt: 0.035; waterdamptransmissie / waterdampdiffusie weerstandsfactor: MU1; luchtstroomweerstand: Afr5; DoP nummer (Declaration of performance): R4208LPCPR; NLRS_C_content_creator: Knauf Insulation; NLRS_C_content_versie: V1.0; diktebereik: 20-200; diktetolerantie: T4; pak (m2): 2.88; pakken / pallet: 12; pallet (m2): 34.56
Classification: 23 Vloeren (Uniformat)
Pset_SlabCommon - LoadBearing: no; PitchAngle: 0 deg
Pset_Floor Schedule Rock4All LOD400 - Type: Floor: NLRS_23_FL_Rock4all_120x600x1200mm

# IfcSlab: Floor:NLRS_23_FL_Rock4all_140x600x1200mm, Floor:NLRS_23_FL_Rock4all_140x600x1200mm:4830
In: Begane grond
Type - PredefinedType: FLOOR; Material: Knauf Insulation_Ecose® steenwol Rock4All 140 mm
Type - Pset_ElementShading - Roughness: 304.8 mm
Type - Pset_ManufacturerTypeInformation - Manufacturer: Knauf Insulation B.V.
Type - Pset_ProductRequirements - Category: Floors
Type - Pset_QuantityTakeOff - Reference: Floor:NLRS_23_FL_Rock4all_140x600x1200mm
Type - Pset_ReinforcementBarPitchOfSlab - Description: Rock4all - 140mm; Reference: Floor:NLRS_23_FL_Rock4all_140x600x1200mm
Type - Pset_SlabCommon - IsExternal: no; ThermalTransmittance: 0.25 kg/K/s3; Reference: Floor:NLRS_23_FL_Rock4all_140x600x1200mm
Type - Pset_Floor Schedule Rock4All LOD400 - warmteweerstand: 4; platen / pak: 3; Assembly Code: 23; Type Image: Raster image: Rock4all_KL.jpg (3); Model: Rock4All is een onbeklede steenwolplaat met ECOSE® Technology Rock4All is een onbeklede steenwolplaat met ECOSE® Technology; Manufacturer: Knauf Insulation B.V.; URL: www.knaufinsulation.nl; Description: Rock4all - 140mm; phone: +31(0)162-421245; email: customerservice.nl@knaufinsulation.com; product URL: https://www.knaufinsulation.nl/producten-van-knauf-insulation/Rock4All; NLRS_C_Code_Brandklasse: A1; warmtegeleidingscoëfficiënt: 0.035; waterdamptransmissie / waterdampdiffusie weerstandsfactor: MU1; luchtstroomweerstand: Afr5; DoP nummer (Declaration of performance): R4208LPCPR; NLRS_C_content_creator: Knauf Insulation; NLRS_C_content_versie: V1.0; diktebereik: 20-200; diktetolerantie: T4; pak (m2): 2.16; pakken / pallet: 12; pallet (m2): 25.92
Classification: 23 Vloeren (Uniformat)
Pset_SlabCommon - LoadBearing: no; PitchAngle: 0 deg
Pset_Floor Schedule Rock4All LOD400 - Type: Floor: NLRS_23_FL_Rock4all_140x600x1200mm

# IfcSlab: Floor:NLRS_23_FL_Rock4all_160x600x1200mm, Floor:NLRS_23_FL_Rock4all_160x600x1200mm:4839
In: Begane grond
Type - PredefinedType: FLOOR; Material: Knauf Insulation_Ecose® steenwol Rock4All 160 mm
Type - Pset_ElementShading - Roughness: 304.8 mm
Type - Pset_ManufacturerTypeInformation - Manufacturer: Knauf Insulation B.V.
Type - Pset_ProductRequirements - Category: Floors
Type - Pset_QuantityTakeOff - Reference: Floor:NLRS_23_FL_Rock4all_160x600x1200mm
Type - Pset_ReinforcementBarPitchOfSlab - Description: Rock4all - 160mm; Reference: Floor:NLRS_23_FL_Rock4all_160x600x1200mm
Type - Pset_SlabCommon - IsExternal: no; Reference: Floor:NLRS_23_FL_Rock4all_160x600x1200mm; ThermalTransmittance: 0.21875 kg/K/s3
Type - Pset_Floor Schedule Rock4All LOD400 - platen / pak: 3; Assembly Code: 23; Type Image: Raster image: Rock4all_KL.jpg (3); Model: Rock4All is een onbeklede steenwolplaat met ECOSE® Technology Rock4All is een onbeklede steenwolplaat met ECOSE® Technology; Manufacturer: Knauf Insulation B.V.; URL: www.knaufinsulation.nl; Description: Rock4all - 160mm; phone: +31(0)162-421245; email: customerservice.nl@knaufinsulation.com; product URL: https://www.knaufinsulation.nl/producten-van-knauf-insulation/Rock4All; warmteweerstand: 4.55; NLRS_C_Code_Brandklasse: A1; warmtegeleidingscoëfficiënt: 0.035; waterdamptransmissie / waterdampdiffusie weerstandsfactor: MU1; luchtstroomweerstand: Afr5; DoP nummer (Declaration of performance): R4208LPCPR; NLRS_C_content_creator: Knauf Insulation; NLRS_C_content_versie: V1.0; diktebereik: 20-200; diktetolerantie: T4; pak (m2): 2.156; pakken / pallet: 12; pallet (m2): 25.92
Classification: 23 Vloeren (Uniformat)
Pset_SlabCommon - LoadBearing: no; PitchAngle: 0 deg
Pset_Floor Schedule Rock4All LOD400 - Type: Floor: NLRS_23_FL_Rock4all_160x600x1200mm

# IfcSlab: Floor:NLRS_23_FL_Rock4all_40x600x1200mm, Floor:NLRS_23_FL_Rock4all_40x600x1200mm:2452
In: Begane grond
Type - PredefinedType: FLOOR; Material: Knauf Insulation_Ecose® steenwol Rock4All 40 mm
Type - Pset_ElementShading - Roughness: 304.8 mm
Type - Pset_ManufacturerTypeInformation - Manufacturer: Knauf Insulation B.V.
Type - Pset_ProductRequirements - Category: Floors
Type - Pset_QuantityTakeOff - Reference: Floor:NLRS_23_FL_Rock4all_40x600x1200mm
Type - Pset_ReinforcementBarPitchOfSlab - Description: Rock4all - 40mm; Reference: Floor:NLRS_23_FL_Rock4all_40x600x1200mm
Type - Pset_SlabCommon - IsExternal: no; Reference: Floor:NLRS_23_FL_Rock4all_40x600x1200mm; ThermalTransmittance: 0.875 kg/K/s3
Type - Pset_Floor Schedule Rock4All LOD400 - Assembly Code: 23; Type Image: Raster image: Rock4all_KL.jpg (3); Model: Rock4All is een onbeklede steenwolplaat met ECOSE® Technology Rock4All is een onbeklede steenwolplaat met ECOSE® Technology; Manufacturer: Knauf Insulation B.V.; URL: www.knaufinsulation.nl; Description: Rock4all - 40mm; phone: +31(0)162-421245; email: customerservice.nl@knaufinsulation.com; product URL: https://www.knaufinsulation.nl/producten-van-knauf-insulation/Rock4All; warmteweerstand: 1.1; NLRS_C_Code_Brandklasse: A1; warmtegeleidingscoëfficiënt: 0.035; waterdamptransmissie / waterdampdiffusie weerstandsfactor: MU1; luchtstroomweerstand: Afr5; DoP nummer (Declaration of performance): R4208LPCPR; NLRS_C_content_creator: Knauf Insulation; NLRS_C_content_versie: V1.0; diktebereik: 20-200; diktetolerantie: T2; platen / pak: 12; pak (m2): 8.64; pakken / pallet: 12; pallet (m2): 103.68
Classification: 23 Vloeren (Uniformat)
Pset_SlabCommon - LoadBearing: no; PitchAngle: 0 deg
Pset_Floor Schedule Rock4All LOD400 - Type: Floor: NLRS_23_FL_Rock4all_40x600x1200mm

# IfcSlab: Floor:NLRS_23_FL_Rock4all_50x600x1200mm, Floor:NLRS_23_FL_Rock4all_50x600x1200mm:2487
In: Begane grond
Type - PredefinedType: FLOOR; Material: Knauf Insulation_Ecose® steenwol Rock4All 50 mm
Type - Pset_ElementShading - Roughness: 304.8 mm
Type - Pset_ManufacturerTypeInformation - Manufacturer: Knauf Insulation B.V.
Type - Pset_ProductRequirements - Category: Floors
Type - Pset_QuantityTakeOff - Reference: Floor:NLRS_23_FL_Rock4all_50x600x1200mm
Type - Pset_ReinforcementBarPitchOfSlab - Description: Rock4all - 50mm; Reference: Floor:NLRS_23_FL_Rock4all_50x600x1200mm
Type - Pset_SlabCommon - IsExternal: no; ThermalTransmittance: 0.7 kg/K/s3; Reference: Floor:NLRS_23_FL_Rock4all_50x600x1200mm
Type - Pset_Floor Schedule Rock4All LOD400 - platen / pak: 10; Assembly Code: 23; Type Image: Raster image: Rock4all_KL.jpg (3); Model: Rock4All is een onbeklede steenwolplaat met ECOSE® Technology Rock4All is een onbeklede steenwolplaat met ECOSE® Technology; Manufacturer: Knauf Insulation B.V.; URL: www.knaufinsulation.nl; Description: Rock4all - 50mm; phone: +31(0)162-421245; email: customerservice.nl@knaufinsulation.com; product URL: https://www.knaufinsulation.nl/producten-van-knauf-insulation/Rock4All; warmteweerstand: 1.4; NLRS_C_Code_Brandklasse: A1; warmtegeleidingscoëfficiënt: 0.035; waterdamptransmissie / waterdampdiffusie weerstandsfactor: MU1; luchtstroomweerstand: Afr5; DoP nummer (Declaration of performance): R4208LPCPR; NLRS_C_content_creator: Knauf Insulation; NLRS_C_content_versie: V1.0; diktebereik: 20-200; diktetolerantie: T4; pak (m2): 7.2; pakken / pallet: 12; pallet (m2): 86.4
Classification: 23 Vloeren (Uniformat)
Pset_SlabCommon - LoadBearing: no; PitchAngle: 0 deg
Pset_Floor Schedule Rock4All LOD400 - Type: Floor: NLRS_23_FL_Rock4all_50x600x1200mm

# IfcSlab: Floor:NLRS_23_FL_Rock4all_60x600x1200mm, Floor:NLRS_23_FL_Rock4all_60x600x1200mm:2494
In: Begane grond
Type - PredefinedType: FLOOR; Material: Knauf Insulation_Ecose® steenwol Rock4All 60 mm
Type - Pset_ElementShading - Roughness: 304.8 mm
Type - Pset_ManufacturerTypeInformation - Manufacturer: Knauf Insulation B.V.
Type - Pset_ProductRequirements - Category: Floors
Type - Pset_QuantityTakeOff - Reference: Floor:NLRS_23_FL_Rock4all_60x600x1200mm
Type - Pset_ReinforcementBarPitchOfSlab - Description: Rock4all - 60mm Rock4all - 60mm; Reference: Floor:NLRS_23_FL_Rock4all_60x600x1200mm
Type - Pset_SlabCommon - IsExternal: no; Reference: Floor:NLRS_23_FL_Rock4all_60x600x1200mm; ThermalTransmittance: 0.583333 kg/K/s3
Type - Pset_Floor Schedule Rock4All LOD400 - platen / pak: 8; Assembly Code: 23; Type Image: Raster image: Rock4all_KL.jpg (3); Model: Rock4All is een onbeklede steenwolplaat met ECOSE® Technology Rock4All is een onbeklede steenwolplaat met ECOSE® Technology; Manufacturer: Knauf Insulation B.V.; URL: www.knaufinsulation.nl; Description: Rock4all - 60mm Rock4all - 60mm; phone: +31(0)162-421245; email: customerservice.nl@knaufinsulation.com; product URL: https://www.knaufinsulation.nl/producten-van-knauf-insulation/Rock4All; warmteweerstand: 1.7; NLRS_C_Code_Brandklasse: A1; warmtegeleidingscoëfficiënt: 0.035; waterdamptransmissie / waterdampdiffusie weerstandsfactor: MU1; luchtstroomweerstand: Afr5; DoP nummer (Declaration of performance): R4208LPCPR; NLRS_C_content_creator: Knauf Insulation; NLRS_C_content_versie: V1.0; diktebereik: 20-200; diktetolerantie: T4; pak (m2): 5.76; pakken / pallet: 12; pallet (m2): 69.12
Classification: 23 Vloeren (Uniformat)
Pset_SlabCommon - LoadBearing: no; PitchAngle: 0 deg
Pset_Floor Schedule Rock4All LOD400 - Type: Floor: NLRS_23_FL_Rock4all_60x600x1200mm

# IfcSlab: Floor:NLRS_23_FL_Rock4all_70x600x1200mm, Floor:NLRS_23_FL_Rock4all_70x600x1200mm:2501
In: Begane grond
Type - PredefinedType: FLOOR; Material: Knauf Insulation_Ecose® steenwol Rock4All 70 mm
Type - Pset_ElementShading - Roughness: 304.8 mm
Type - Pset_ManufacturerTypeInformation - Manufacturer: Knauf Insulation B.V.
Type - Pset_ProductRequirements - Category: Floors
Type - Pset_QuantityTakeOff - Reference: Floor:NLRS_23_FL_Rock4all_70x600x1200mm
Type - Pset_ReinforcementBarPitchOfSlab - Description: Rock4all - 70mm; Reference: Floor:NLRS_23_FL_Rock4all_70x600x1200mm
Type - Pset_SlabCommon - IsExternal: no; ThermalTransmittance: 0.5 kg/K/s3; Reference: Floor:NLRS_23_FL_Rock4all_70x600x1200mm
Type - Pset_Floor Schedule Rock4All LOD400 - warmteweerstand: 2; platen / pak: 6; Assembly Code: 23; Type Image: Raster image: Rock4all_KL.jpg (3); Model: Rock4All is een onbeklede steenwolplaat met ECOSE® Technology Rock4All is een onbeklede steenwolplaat met ECOSE® Technology; Manufacturer: Knauf Insulation B.V.; URL: www.knaufinsulation.nl; Description: Rock4all - 70mm; phone: +31(0)162-421245; email: customerservice.nl@knaufinsulation.com; product URL: https://www.knaufinsulation.nl/producten-van-knauf-insulation/Rock4All; NLRS_C_Code_Brandklasse: A1; warmtegeleidingscoëfficiënt: 0.035; waterdamptransmissie / waterdampdiffusie weerstandsfactor: MU1; luchtstroomweerstand: Afr5; DoP nummer (Declaration of performance): R4208LPCPR; NLRS_C_content_creator: Knauf Insulation; NLRS_C_content_versie: V1.0; diktebereik: 20-200; diktetolerantie: T4; pak (m2): 4.32; pakken / pallet: 12; pallet (m2): 51.84
Classification: 23 Vloeren (Uniformat)
Pset_SlabCommon - LoadBearing: no; PitchAngle: 0 deg
Pset_Floor Schedule Rock4All LOD400 - Type: Floor: NLRS_23_FL_Rock4all_70x600x1200mm

# IfcSlab: Floor:NLRS_23_FL_Rock4all_80x600x1200mm, Floor:NLRS_23_FL_Rock4all_80x600x1200mm:4345
In: Begane grond
Type - PredefinedType: FLOOR; Material: Knauf Insulation_Ecose® steenwol Rock4All 80 mm
Type - Pset_ElementShading - Roughness: 304.8 mm
Type - Pset_ManufacturerTypeInformation - Manufacturer: Knauf Insulation B.V.
Type - Pset_ProductRequirements - Category: Floors
Type - Pset_QuantityTakeOff - Reference: Floor:NLRS_23_FL_Rock4all_80x600x1200mm
Type - Pset_ReinforcementBarPitchOfSlab - Description: Rock4all - 80mm; Reference: Floor:NLRS_23_FL_Rock4all_80x600x1200mm
Type - Pset_SlabCommon - IsExternal: no; Reference: Floor:NLRS_23_FL_Rock4all_80x600x1200mm; ThermalTransmittance: 0.4375 kg/K/s3
Type - Pset_Floor Schedule Rock4All LOD400 - platen / pak: 6; Assembly Code: 23; Type Image: Raster image: Rock4all_KL.jpg (3); Model: Rock4All is een onbeklede steenwolplaat met ECOSE® Technology Rock4All is een onbeklede steenwolplaat met ECOSE® Technology; Manufacturer: Knauf Insulation B.V.; URL: www.knaufinsulation.nl; Description: Rock4all - 80mm; phone: +31(0)162-421245; email: customerservice.nl@knaufinsulation.com; product URL: https://www.knaufinsulation.nl/producten-van-knauf-insulation/Rock4All; warmteweerstand: 2.25; NLRS_C_Code_Brandklasse: A1; warmtegeleidingscoëfficiënt: 0.035; waterdamptransmissie / waterdampdiffusie weerstandsfactor: MU1; luchtstroomweerstand: Afr5; DoP nummer (Declaration of performance): R4208LPCPR; NLRS_C_content_creator: Knauf Insulation; NLRS_C_content_versie: V1.0; diktebereik: 20-200; diktetolerantie: T4; pak (m2): 4.32; pakken / pallet: 12; pallet (m2): 51.84
Classification: 23 Vloeren (Uniformat)
Pset_SlabCommon - LoadBearing: no; PitchAngle: 0 deg
Pset_Floor Schedule Rock4All LOD400 - Type: Floor: NLRS_23_FL_Rock4all_80x600x1200mm

# IfcSlab: Floor:NLRS_23_FL_Rock4all_90x600x1200mm, Floor:NLRS_23_FL_Rock4all_90x600x1200mm:4387
In: Begane grond
Type - PredefinedType: FLOOR; Material: Knauf Insulation_Ecose® steenwol Rock4All 90 mm
Type - Pset_ElementShading - Roughness: 304.8 mm
Type - Pset_ManufacturerTypeInformation - Manufacturer: Knauf Insulation B.V.
Type - Pset_ProductRequirements - Category: Floors
Type - Pset_QuantityTakeOff - Reference: Floor:NLRS_23_FL_Rock4all_90x600x1200mm
Type - Pset_ReinforcementBarPitchOfSlab - Description: Rock4all - 90mm; Reference: Floor:NLRS_23_FL_Rock4all_90x600x1200mm
Type - Pset_SlabCommon - IsExternal: no; Reference: Floor:NLRS_23_FL_Rock4all_90x600x1200mm; ThermalTransmittance: 0.388889 kg/K/s3
Type - Pset_Floor Schedule Rock4All LOD400 - platen / pak: 5; Assembly Code: 23; Type Image: Raster image: Rock4all_KL.jpg (3); Model: Rock4All is een onbeklede steenwolplaat met ECOSE® Technology Rock4All is een onbeklede steenwolplaat met ECOSE® Technology; Manufacturer: Knauf Insulation B.V.; URL: www.knaufinsulation.nl; Description: Rock4all - 90mm; phone: +31(0)162-421245; email: customerservice.nl@knaufinsulation.com; product URL: https://www.knaufinsulation.nl/producten-van-knauf-insulation/Rock4All; warmteweerstand: 2.55; NLRS_C_Code_Brandklasse: A1; warmtegeleidingscoëfficiënt: 0.035; waterdamptransmissie / waterdampdiffusie weerstandsfactor: MU1; luchtstroomweerstand: Afr5; DoP nummer (Declaration of performance): R4208LPCPR; NLRS_C_content_creator: Knauf Insulation; NLRS_C_content_versie: V1.0; diktebereik: 20-200; diktetolerantie: T4; pak (m2): 3.6; pakken / pallet: 12; pallet (m2): 43.2
Classification: 23 Vloeren (Uniformat)
Pset_SlabCommon - LoadBearing: no; PitchAngle: 0 deg
Pset_Floor Schedule Rock4All LOD400 - Type: Floor: NLRS_23_FL_Rock4all_90x600x1200mm

# IfcWallStandardCase: Basic Wall:NLRS_22_WA_Rock4all_100x600x1200mm (3)
In: Begane grond
Type - PredefinedType: STANDARD; Material: Knauf Insulation_Ecose® steenwol Rock4All 100 mm
Type - Pset_ElementShading - Roughness: 304.8 mm
Type - Pset_ManufacturerTypeInformation - Manufacturer: Knauf Insulation B.V.
Type - Pset_ProductRequirements - Category: Walls
Type - Pset_QuantityTakeOff - Reference: Basic Wall:NLRS_22_WA_Rock4all_100x600x1200mm
Type - Pset_ReinforcementBarPitchOfWall - Description: Rock4all - 100mm; Reference: Basic Wall:NLRS_22_WA_Rock4all_100x600x1200mm
Type - Pset_WallCommon - IsExternal: no; Reference: Basic Wall:NLRS_22_WA_Rock4all_100x600x1200mm; ThermalTransmittance: 0.35 kg/K/s3
Type - Pset_Wall Schedule Rock4All LOD400 - platen / pak: 5; Assembly Code: 22; Type Image: Raster image: Rock4all_KL.jpg (3); Model: Acoustifit is een onbeklede glaswolplaat met ECOSE® Technology.; Manufacturer: Knauf Insulation B.V.; URL: www.knaufinsulation.nl; Description: Rock4all - 100mm; phone: +31(0)162-421245; email: customerservice.nl@knaufinsulation.com; product URL: https://www.knaufinsulation.nl/producten-van-knauf-insulation/Rock4All; warmteweerstand: 2.85; NLRS_C_Code_Brandklasse: A1; warmtegeleidingscoëfficiënt: 0.035; waterdamptransmissie / waterdampdiffusie weerstandsfactor: MU1; luchtstroomweerstand: Afr5; DoP nummer (Declaration of performance): R4208LPCPR; NLRS_C_content_creator: Cadix; NLRS_C_content_versie: V1.0; diktebereik: 20-200; diktetolerantie: T4; pak (m2): 3.6; pakken / pallet: 12; pallet (m2): 43.2
Classification: 22 Binnenwanden (Uniformat)
Pset_WallCommon - ExtendToStructure: no; LoadBearing: no
Pset_Wall Schedule Rock4All LOD400 - Type: Basic Wall: NLRS_22_WA_Rock4all_100x600x1200mm
Name (Basic Wall:NLRS_22_WA_Rock4all_100x600x1200mm:...)
2473
2474
2475

# IfcWallStandardCase: Basic Wall:NLRS_22_WA_Rock4all_120x600x1200mm (3)
In: Begane grond
Type - PredefinedType: STANDARD; Material: Knauf Insulation_Ecose® steenwol Rock4All 120 mm
Type - Pset_ElementShading - Roughness: 304.8 mm
Type - Pset_ManufacturerTypeInformation - Manufacturer: Knauf Insulation B.V.
Type - Pset_ProductRequirements - Category: Walls
Type - Pset_QuantityTakeOff - Reference: Basic Wall:NLRS_22_WA_Rock4all_120x600x1200mm
Type - Pset_ReinforcementBarPitchOfWall - Description: Rock4all - 120mm; Reference: Basic Wall:NLRS_22_WA_Rock4all_120x600x1200mm
Type - Pset_WallCommon - IsExternal: no; Reference: Basic Wall:NLRS_22_WA_Rock4all_120x600x1200mm; ThermalTransmittance: 0.291667 kg/K/s3
Type - Pset_Wall Schedule Rock4All LOD400 - Assembly Code: 22; Type Image: Raster image: Rock4all_KL.jpg (3); Model: Acoustifit is een onbeklede glaswolplaat met ECOSE® Technology.; Manufacturer: Knauf Insulation B.V.; URL: www.knaufinsulation.nl; Description: Rock4all - 120mm; phone: +31(0)162-421245; email: customerservice.nl@knaufinsulation.com; product URL: https://www.knaufinsulation.nl/producten-van-knauf-insulation/Rock4All; warmteweerstand: 3.4; NLRS_C_Code_Brandklasse: A1; warmtegeleidingscoëfficiënt: 0.035; waterdamptransmissie / waterdampdiffusie weerstandsfactor: MU1; luchtstroomweerstand: Afr5; DoP nummer (Declaration of performance): R4208LPCPR; NLRS_C_content_creator: Cadix; NLRS_C_content_versie: V1.0; diktebereik: 20-200; diktetolerantie: T4; platen / pak: 4; pak (m2): 2.88; pakken / pallet: 12; pallet (m2): 34.56
Classification: 22 Binnenwanden (Uniformat)
Pset_WallCommon - ExtendToStructure: no; LoadBearing: no
Pset_Wall Schedule Rock4All LOD400 - Type: Basic Wall: NLRS_22_WA_Rock4all_120x600x1200mm
Name (Basic Wall:NLRS_22_WA_Rock4all_120x600x1200mm:...)
2476
2477
2478

# IfcWallStandardCase: Basic Wall:NLRS_22_WA_Rock4all_140x600x1200mm (3)
In: Begane grond
Type - PredefinedType: STANDARD; Material: Knauf Insulation_Ecose® steenwol Rock4All 140 mm
Type - Pset_ElementShading - Roughness: 304.8 mm
Type - Pset_ManufacturerTypeInformation - Manufacturer: Knauf Insulation B.V.
Type - Pset_ProductRequirements - Category: Walls
Type - Pset_QuantityTakeOff - Reference: Basic Wall:NLRS_22_WA_Rock4all_140x600x1200mm
Type - Pset_ReinforcementBarPitchOfWall - Description: Rock4all - 140mm; Reference: Basic Wall:NLRS_22_WA_Rock4all_140x600x1200mm
Type - Pset_WallCommon - IsExternal: no; Reference: Basic Wall:NLRS_22_WA_Rock4all_140x600x1200mm; ThermalTransmittance: 0.25 kg/K/s3
Type - Pset_Wall Schedule Rock4All LOD400 - Assembly Code: 22; Type Image: Raster image: Rock4all_KL.jpg (3); Model: Acoustifit is een onbeklede glaswolplaat met ECOSE® Technology.; Manufacturer: Knauf Insulation B.V.; URL: www.knaufinsulation.nl; Description: Rock4all - 140mm; phone: +31(0)162-421245; email: customerservice.nl@knaufinsulation.com; product URL: https://www.knaufinsulation.nl/producten-van-knauf-insulation/Rock4All; warmteweerstand: 4; NLRS_C_Code_Brandklasse: A1; warmtegeleidingscoëfficiënt: 0.035; waterdamptransmissie / waterdampdiffusie weerstandsfactor: MU1; luchtstroomweerstand: Afr5; DoP nummer (Declaration of performance): R4208LPCPR; NLRS_C_content_creator: Cadix; NLRS_C_content_versie: V1.0; diktebereik: 20-200; diktetolerantie: T4; platen / pak: 3; pak (m2): 2.16; pakken / pallet: 12; pallet (m2): 25.92
Classification: 22 Binnenwanden (Uniformat)
Pset_WallCommon - ExtendToStructure: no; LoadBearing: no
Pset_Wall Schedule Rock4All LOD400 - Type: Basic Wall: NLRS_22_WA_Rock4all_140x600x1200mm
Name (Basic Wall:NLRS_22_WA_Rock4all_140x600x1200mm:...)
2479
2480
2481

# IfcWallStandardCase: Basic Wall:NLRS_22_WA_Rock4all_160x600x1200mm (3)
In: Begane grond
Type - PredefinedType: STANDARD; Material: Knauf Insulation_Ecose® steenwol Rock4All 160 mm
Type - Pset_ElementShading - Roughness: 304.8 mm
Type - Pset_ManufacturerTypeInformation - Manufacturer: Knauf Insulation B.V.
Type - Pset_ProductRequirements - Category: Walls
Type - Pset_QuantityTakeOff - Reference: Basic Wall:NLRS_22_WA_Rock4all_160x600x1200mm
Type - Pset_ReinforcementBarPitchOfWall - Description: Rock4all - 160mm; Reference: Basic Wall:NLRS_22_WA_Rock4all_160x600x1200mm
Type - Pset_WallCommon - IsExternal: no; Reference: Basic Wall:NLRS_22_WA_Rock4all_160x600x1200mm; ThermalTransmittance: 0.21875 kg/K/s3
Type - Pset_Wall Schedule Rock4All LOD400 - platen / pak: 3; Assembly Code: 22; Type Image: Raster image: Rock4all_KL.jpg (3); Model: Acoustifit is een onbeklede glaswolplaat met ECOSE® Technology.; Manufacturer: Knauf Insulation B.V.; URL: www.knaufinsulation.nl; Description: Rock4all - 160mm; phone: +31(0)162-421245; email: customerservice.nl@knaufinsulation.com; product URL: https://www.knaufinsulation.nl/producten-van-knauf-insulation/Rock4All; warmteweerstand: 4.55; NLRS_C_Code_Brandklasse: A1; warmtegeleidingscoëfficiënt: 0.035; waterdamptransmissie / waterdampdiffusie weerstandsfactor: MU1; luchtstroomweerstand: Afr5; DoP nummer (Declaration of performance): R4208LPCPR; NLRS_C_content_creator: Cadix; NLRS_C_content_versie: V1.0; diktebereik: 20-200; diktetolerantie: T4; pak (m2): 2.16; pakken / pallet: 12; pallet (m2): 25.92
Classification: 22 Binnenwanden (Uniformat)
Pset_WallCommon - ExtendToStructure: no; LoadBearing: no
Pset_Wall Schedule Rock4All LOD400 - Type: Basic Wall: NLRS_22_WA_Rock4all_160x600x1200mm
Name (Basic Wall:NLRS_22_WA_Rock4all_160x600x1200mm:...)
2482
2483
2484

# IfcWallStandardCase: Basic Wall:NLRS_22_WA_Rock4all_50xx600x1200mm (3)
In: Begane grond
Type - PredefinedType: STANDARD; Material: Knauf Insulation_Ecose® steenwol Rock4All 50 mm
Type - Pset_ElementShading - Roughness: 304.8 mm
Type - Pset_ManufacturerTypeInformation - Manufacturer: Knauf Insulation B.V.
Type - Pset_ProductRequirements - Category: Walls
Type - Pset_QuantityTakeOff - Reference: Basic Wall:NLRS_22_WA_Rock4all_50xx600x1200mm
Type - Pset_ReinforcementBarPitchOfWall - Description: Rock4all - 60mm; Reference: Basic Wall:NLRS_22_WA_Rock4all_50xx600x1200mm
Type - Pset_WallCommon - IsExternal: no; Reference: Basic Wall:NLRS_22_WA_Rock4all_50xx600x1200mm; ThermalTransmittance: 0.7 kg/K/s3
Type - Pset_Wall Schedule Rock4All LOD400 - Assembly Code: 22; Type Image: Raster image: Rock4all_KL.jpg (3); Model: Acoustifit is een onbeklede glaswolplaat met ECOSE® Technology.; Manufacturer: Knauf Insulation B.V.; URL: www.knaufinsulation.nl; Description: Rock4all - 60mm; phone: +31(0)162-421245; email: customerservice.nl@knaufinsulation.com; product URL: https://www.knaufinsulation.nl/producten-van-knauf-insulation/Rock4All; warmteweerstand: 1.7; NLRS_C_Code_Brandklasse: A1; warmtegeleidingscoëfficiënt: 0.035; waterdamptransmissie / waterdampdiffusie weerstandsfactor: MU1; luchtstroomweerstand: Afr5; DoP nummer (Declaration of performance): R4208LPCPR; NLRS_C_content_creator: Cadix; NLRS_C_content_versie: V1.0; diktebereik: 20-200; diktetolerantie: T4; platen / pak: 8; pak (m2): 5.76; pakken / pallet: 12; pallet (m2): 69.12
Classification: 22 Binnenwanden (Uniformat)
Pset_WallCommon - ExtendToStructure: no; LoadBearing: no
Pset_Wall Schedule Rock4All LOD400 - Type: Basic Wall: NLRS_22_WA_Rock4all_50xx600x1200mm
Name (Basic Wall:NLRS_22_WA_Rock4all_50xx600x1200mm:...)
2458
2459
2460

# IfcWallStandardCase: Basic Wall:NLRS_22_WA_Rock4all_70x600x1200mm (3)
In: Begane grond
Type - PredefinedType: STANDARD; Material: Knauf Insulation_Ecose® steenwol Rock4All 70 mm
Type - Pset_ElementShading - Roughness: 304.8 mm
Type - Pset_ManufacturerTypeInformation - Manufacturer: Knauf Insulation B.V.
Type - Pset_ProductRequirements - Category: Walls
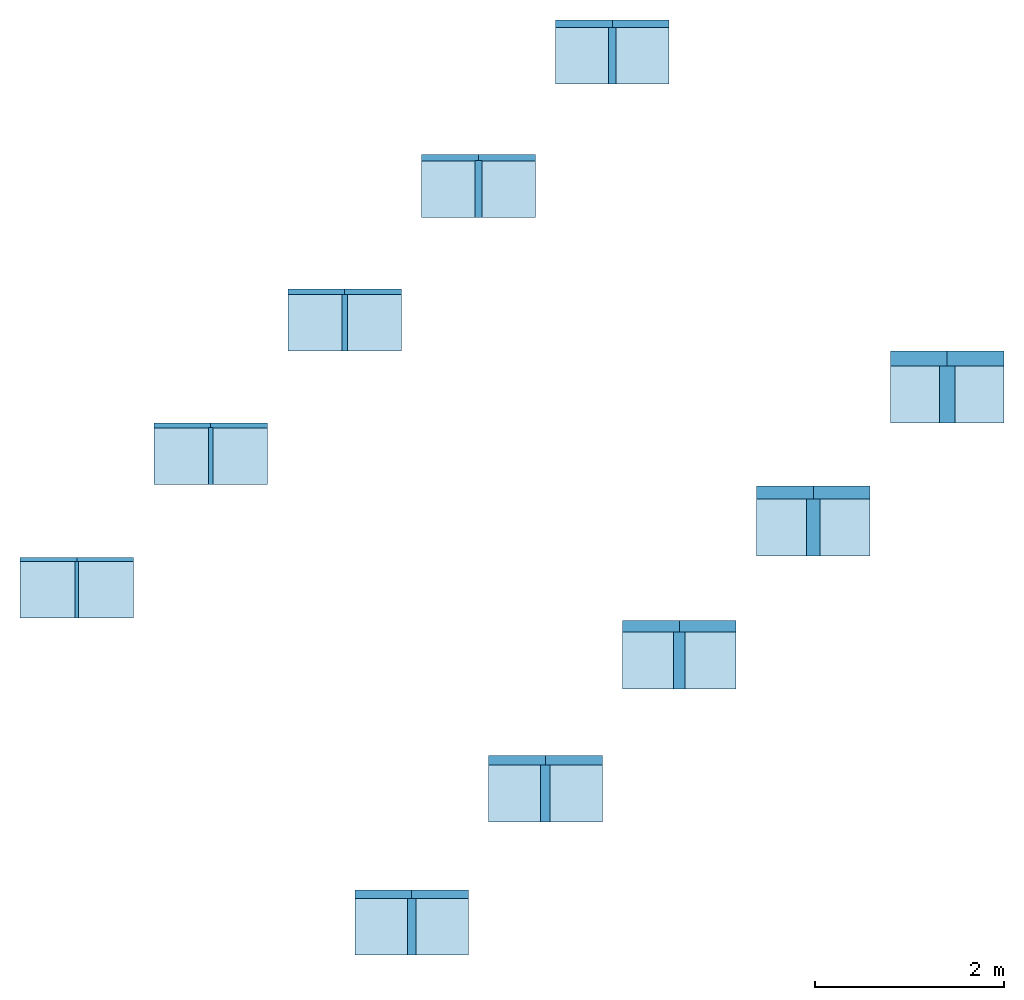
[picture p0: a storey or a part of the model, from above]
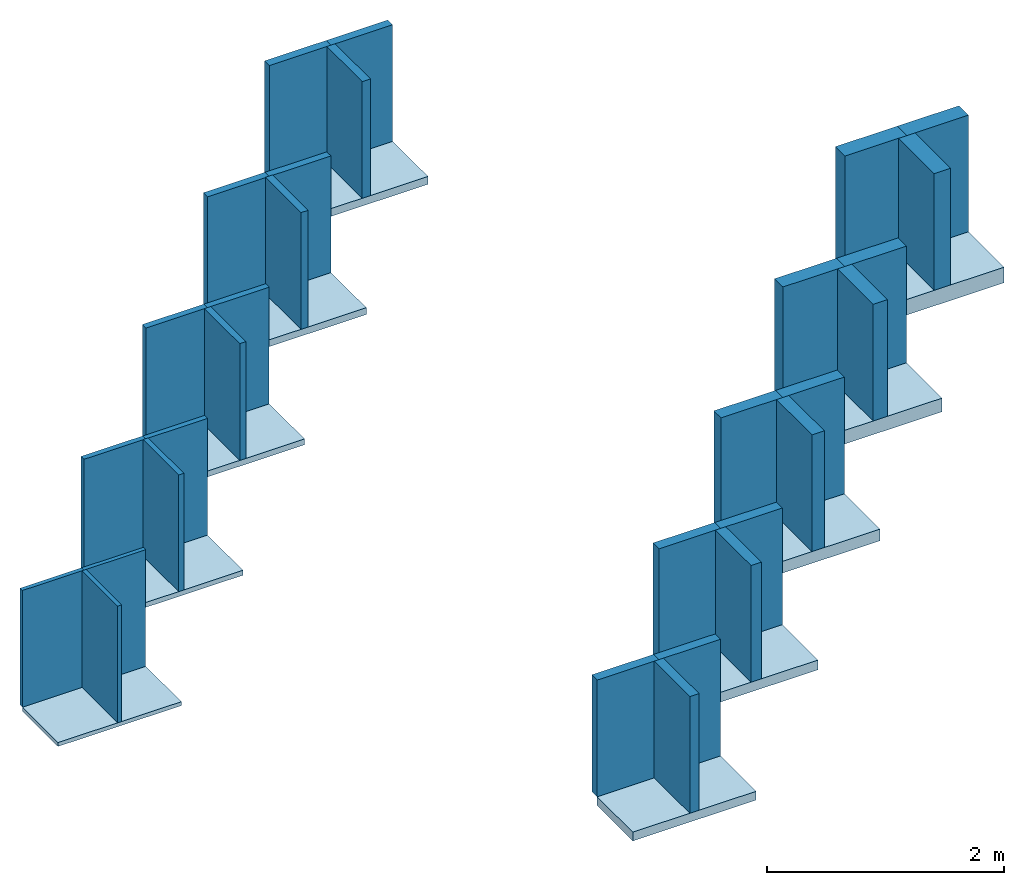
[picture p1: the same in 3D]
Properties of the parts of a building model (IFC2X3), part 2 of 2

# IfcWallStandardCase: Basic Wall:NLRS_22_WA_Rock4all_70x600x1200mm (3)
Type - Pset_QuantityTakeOff - Reference: Basic Wall:NLRS_22_WA_Rock4all_70x600x1200mm
Type - Pset_ReinforcementBarPitchOfWall - Description: Rock4all - 70mm; Reference: Basic Wall:NLRS_22_WA_Rock4all_70x600x1200mm
Type - Pset_WallCommon - IsExternal: no; Reference: Basic Wall:NLRS_22_WA_Rock4all_70x600x1200mm; ThermalTransmittance: 0.5 kg/K/s3
Type - Pset_Wall Schedule Rock4All LOD400 - Assembly Code: 22; Type Image: Raster image: Rock4all_KL.jpg (3); Model: Acoustifit is een onbeklede glaswolplaat met ECOSE® Technology.; Manufacturer: Knauf Insulation B.V.; URL: www.knaufinsulation.nl; Description: Rock4all - 70mm; phone: +31(0)162-421245; email: customerservice.nl@knaufinsulation.com; product URL: https://www.knaufinsulation.nl/producten-van-knauf-insulation/Rock4All; warmteweerstand: 2; NLRS_C_Code_Brandklasse: A1; warmtegeleidingscoëfficiënt: 0.035; waterdamptransmissie / waterdampdiffusie weerstandsfactor: MU1; luchtstroomweerstand: Afr5; DoP nummer (Declaration of performance): R4208LPCPR; NLRS_C_content_creator: Cadix; NLRS_C_content_versie: V1.0; diktebereik: 20-200; diktetolerantie: T4; platen / pak: 6; pak (m2): 4.32; pakken / pallet: 12; pallet (m2): 51.84
Classification: 22 Binnenwanden (Uniformat)
Pset_WallCommon - ExtendToStructure: no; LoadBearing: no
Pset_Wall Schedule Rock4All LOD400 - Type: Basic Wall: NLRS_22_WA_Rock4all_70x600x1200mm
Name (Basic Wall:NLRS_22_WA_Rock4all_70x600x1200mm:...)
2464
2465
2466

# IfcWallStandardCase: Basic Wall:NLRS_22_WA_Rock4all_80x600x1200mm (3)
In: Begane grond
Type - PredefinedType: STANDARD; Material: Knauf Insulation_Ecose® steenwol Rock4All 80 mm
Type - Pset_ElementShading - Roughness: 304.8 mm
Type - Pset_ManufacturerTypeInformation - Manufacturer: Knauf Insulation B.V.
Type - Pset_ProductRequirements - Category: Walls
Type - Pset_QuantityTakeOff - Reference: Basic Wall:NLRS_22_WA_Rock4all_80x600x1200mm
Type - Pset_ReinforcementBarPitchOfWall - Description: Rock4all - 80mm; Reference: Basic Wall:NLRS_22_WA_Rock4all_80x600x1200mm
Type - Pset_WallCommon - IsExternal: no; Reference: Basic Wall:NLRS_22_WA_Rock4all_80x600x1200mm; ThermalTransmittance: 0.4375 kg/K/s3
Type - Pset_Wall Schedule Rock4All LOD400 - platen / pak: 6; Assembly Code: 22; Type Image: Raster image: Rock4all_KL.jpg (3); Model: Acoustifit is een onbeklede glaswolplaat met ECOSE® Technology.; Manufacturer: Knauf Insulation B.V.; URL: www.knaufinsulation.nl; Description: Rock4all - 80mm; phone: +31(0)162-421245; email: customerservice.nl@knaufinsulation.com; product URL: https://www.knaufinsulation.nl/producten-van-knauf-insulation/Rock4All; warmteweerstand: 2.25; NLRS_C_Code_Brandklasse: A1; warmtegeleidingscoëfficiënt: 0.035; waterdamptransmissie / waterdampdiffusie weerstandsfactor: MU1; luchtstroomweerstand: Afr5; DoP nummer (Declaration of performance): R4208LPCPR; NLRS_C_content_creator: Cadix; NLRS_C_content_versie: V1.0; diktebereik: 20-200; diktetolerantie: T4; pak (m2): 4.32; pakken / pallet: 12; pallet (m2): 51.84
Classification: 22 Binnenwanden (Uniformat)
Pset_WallCommon - ExtendToStructure: no; LoadBearing: no
Pset_Wall Schedule Rock4All LOD400 - Type: Basic Wall: NLRS_22_WA_Rock4all_80x600x1200mm
Name (Basic Wall:NLRS_22_WA_Rock4all_80x600x1200mm:...)
2467
2468
2469

# IfcWallStandardCase: Basic Wall:NLRS_22_WA_Rock4all_90x100x1200mm (3)
In: Begane grond
Type - PredefinedType: STANDARD; Material: Knauf Insulation_Ecose® steenwol Rock4All 90 mm
Type - Pset_ElementShading - Roughness: 304.8 mm
Type - Pset_ManufacturerTypeInformation - Manufacturer: Knauf Insulation B.V.
Type - Pset_ProductRequirements - Category: Walls
Type - Pset_QuantityTakeOff - Reference: Basic Wall:NLRS_22_WA_Rock4all_90x100x1200mm
Type - Pset_ReinforcementBarPitchOfWall - Description: Rock4all - 90mm; Reference: Basic Wall:NLRS_22_WA_Rock4all_90x100x1200mm
Type - Pset_WallCommon - IsExternal: no; Reference: Basic Wall:NLRS_22_WA_Rock4all_90x100x1200mm; ThermalTransmittance: 0.388889 kg/K/s3
Type - Pset_Wall Schedule Rock4All LOD400 - Assembly Code: 22; Type Image: Raster image: Rock4all_KL.jpg (3); Model: Acoustifit is een onbeklede glaswolplaat met ECOSE® Technology.; Manufacturer: Knauf Insulation B.V.; URL: www.knaufinsulation.nl; Description: Rock4all - 90mm; phone: +31(0)162-421245; email: customerservice.nl@knaufinsulation.com; product URL: https://www.knaufinsulation.nl/producten-van-knauf-insulation/Rock4All; warmteweerstand: 2.55; NLRS_C_Code_Brandklasse: A1; warmtegeleidingscoëfficiënt: 0.035; waterdamptransmissie / waterdampdiffusie weerstandsfactor: MU1; luchtstroomweerstand: Afr5; DoP nummer (Declaration of performance): R4208LPCPR; NLRS_C_content_creator: Cadix; NLRS_C_content_versie: V1.0; diktebereik: 20-200; diktetolerantie: T4; platen / pak: 5; pak (m2): 3.6; pakken / pallet: 12; pallet (m2): 43.2
Classification: 22 Binnenwanden (Uniformat)
Pset_WallCommon - ExtendToStructure: no; LoadBearing: no
Pset_Wall Schedule Rock4All LOD400 - Type: Basic Wall: NLRS_22_WA_Rock4all_90x100x1200mm
Name (Basic Wall:NLRS_22_WA_Rock4all_90x100x1200mm:...)
2470
2471
2472

# IfcWallStandardCase: Basic Wall:NLRS_22_WA__Rock4all_40x600x1200mm (3)
In: Begane grond
Type - PredefinedType: STANDARD; Material: Knauf Insulation_Ecose® steenwol Rock4All 40 mm
Type - Pset_ElementShading - Roughness: 304.8 mm
Type - Pset_ManufacturerTypeInformation - Manufacturer: Knauf Insulation B.V.
Type - Pset_ProductRequirements - Category: Walls
Type - Pset_QuantityTakeOff - Reference: Basic Wall:NLRS_22_WA__Rock4all_40x600x1200mm
Type - Pset_ReinforcementBarPitchOfWall - Description: Rock4all - 40mm; Reference: Basic Wall:NLRS_22_WA__Rock4all_40x600x1200mm
Type - Pset_WallCommon - Reference: Basic Wall:NLRS_22_WA__Rock4all_40x600x1200mm; ThermalTransmittance: 0.875 kg/K/s3; IsExternal: no
Type - Pset_Wall Schedule Rock4All LOD400 - Assembly Code: 22; Type Image: Raster image: Rock4all_KL.jpg (3); Model: Acoustifit is een onbeklede glaswolplaat met ECOSE® Technology.; Manufacturer: Knauf Insulation B.V.; URL: www.knaufinsulation.nl; Description: Rock4all - 40mm; phone: +31(0)162-421245; email: customerservice.nl@knaufinsulation.com; product URL: https://www.knaufinsulation.nl/producten-van-knauf-insulation/Rock4All; warmteweerstand: 1.1; NLRS_C_Code_Brandklasse: A1; warmtegeleidingscoëfficiënt: 0.035; waterdamptransmissie / waterdampdiffusie weerstandsfactor: MU1; luchtstroomweerstand: Afr5; DoP nummer (Declaration of performance): R4208LPCPR; NLRS_C_content_creator: Cadix; NLRS_C_content_versie: V1.0; diktebereik: 20-200; diktetolerantie: T4; platen / pak: 12; pak (m2): 8.64; pakken / pallet: 12; pallet (m2): 103.68
Classification: 22 Binnenwanden (Uniformat)
Pset_WallCommon - ExtendToStructure: no; LoadBearing: no
Pset_Wall Schedule Rock4All LOD400 - Type: Basic Wall: NLRS_22_WA__Rock4all_40x600x1200mm
Name (Basic Wall:NLRS_22_WA__Rock4all_40x600x1200mm:...)
2447
2448
2457

# IfcWallStandardCase: Basic Wall:NLRS_22_WA__Rock4all_60x600x1200mm (3)
In: Begane grond
Type - PredefinedType: STANDARD; Material: Knauf Insulation_Ecose® steenwol Rock4All 60 mm
Type - Pset_ElementShading - Roughness: 304.8 mm
Type - Pset_ManufacturerTypeInformation - Manufacturer: Knauf Insulation B.V.
Type - Pset_ProductRequirements - Category: Walls
Type - Pset_QuantityTakeOff - Reference: Basic Wall:NLRS_22_WA__Rock4all_60x600x1200mm
Type - Pset_ReinforcementBarPitchOfWall - Description: Rock4all - 50mm; Reference: Basic Wall:NLRS_22_WA__Rock4all_60x600x1200mm
Type - Pset_WallCommon - IsExternal: no; Reference: Basic Wall:NLRS_22_WA__Rock4all_60x600x1200mm; ThermalTransmittance: 0.583333 kg/K/s3
Type - Pset_Wall Schedule Rock4All LOD400 - Assembly Code: 22; Type Image: Raster image: Rock4all_KL.jpg (3); Model: Acoustifit is een onbeklede glaswolplaat met ECOSE® Technology.; Manufacturer: Knauf Insulation B.V.; URL: www.knaufinsulation.nl; Description: Rock4all - 50mm; phone: +31(0)162-421245; email: customerservice.nl@knaufinsulation.com; product URL: https://www.knaufinsulation.nl/producten-van-knauf-insulation/Rock4All; warmteweerstand: 1.4; NLRS_C_Code_Brandklasse: A1; warmtegeleidingscoëfficiënt: 0.035; waterdamptransmissie / waterdampdiffusie weerstandsfactor: MU1; luchtstroomweerstand: Afr5; DoP nummer (Declaration of performance): R4208LPCPR; NLRS_C_content_creator: Cadix; NLRS_C_content_versie: V1.0; diktebereik: 20-200; diktetolerantie: T4; platen / pak: 10; pak (m2): 7.2; pakken / pallet: 12; pallet (m2): 86.4
Classification: 22 Binnenwanden (Uniformat)
Pset_WallCommon - ExtendToStructure: no; LoadBearing: no
Pset_Wall Schedule Rock4All LOD400 - Type: Basic Wall: NLRS_22_WA__Rock4all_60x600x1200mm
Name (Basic Wall:NLRS_22_WA__Rock4all_60x600x1200mm:...)
2461
2462
2463
